FUNCTION "Gest Avvisi ed Allarmi" : VOID
TITLE =Gestione Avvisi ed Allarmi
AUTHOR : MassimoZ
FAMILY : NovaSrl
VERSION : 0.1

BEGIN
NETWORK
TITLE ======== Accatastatrice 1 =======

NETWORK
TITLE ======== Avvisi ======

NETWORK
TITLE =Avviso Manca Presenza Pallet al Carico Acc.1

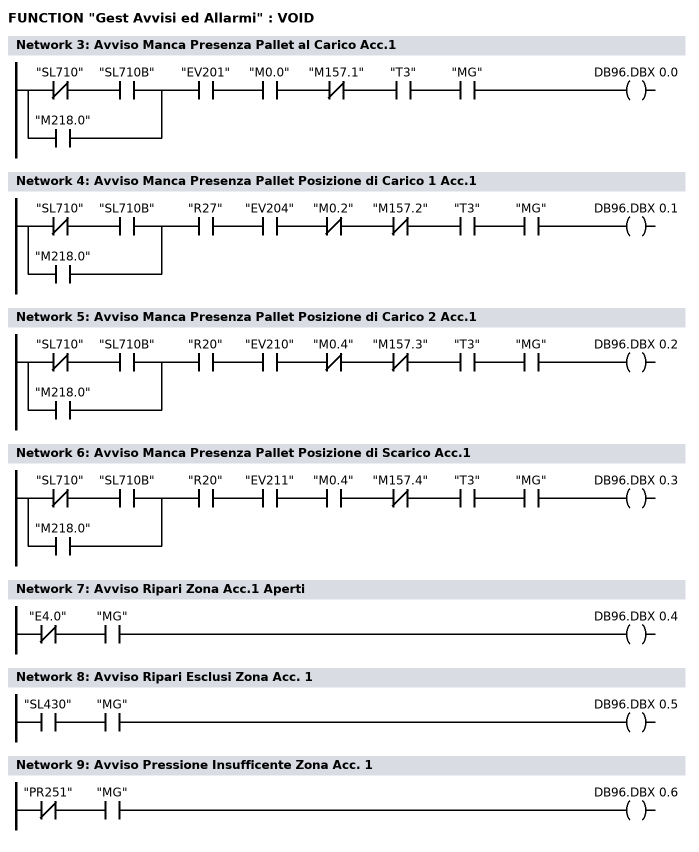
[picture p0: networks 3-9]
      U(    ;
      UN    "SL710";
      U     "SL710B";
      O     "M218.0";
      )     ;
      U     "EV201";
      U     "M0.0";
      UN    "M157.1";
      U     "T3";
      U     "MG";
      =     DB96.DBX    0.0;
NETWORK
TITLE =Avviso Manca Presenza Pallet Posizione di Carico 1 Acc.1

      U(    ;
      UN    "SL710";
      U     "SL710B";
      O     "M218.0";
      )     ;
      U     "R27";
      U     "EV204";
      UN    "M0.2";
      UN    "M157.2";
      U     "T3";
      U     "MG";
      =     DB96.DBX    0.1;
NETWORK
TITLE =Avviso Manca Presenza Pallet Posizione di Carico 2 Acc.1

      U(    ;
      UN    "SL710";
      U     "SL710B";
      O     "M218.0";
      )     ;
      U     "R20";
      U     "EV210";
      UN    "M0.4";
      UN    "M157.3";
      U     "T3";
      U     "MG";
      =     DB96.DBX    0.2;
NETWORK
TITLE =Avviso Manca Presenza Pallet Posizione di Scarico Acc.1

      U(    ;
      UN    "SL710";
      U     "SL710B";
      O     "M218.0";
      )     ;
      U     "R20";
      U     "EV211";
      U     "M0.4";
      UN    "M157.4";
      U     "T3";
      U     "MG";
      =     DB96.DBX    0.3;
NETWORK
TITLE =Avviso Ripari Zona Acc.1 Aperti

      UN    "E4.0";
      U     "MG";
      =     DB96.DBX    0.4;
NETWORK
TITLE =Avviso Ripari Esclusi Zona Acc. 1

      U     "SL430";
      U     "MG";
      =     DB96.DBX    0.5;
NETWORK
TITLE =Avviso Pressione Insufficente Zona Acc. 1

      UN    "PR251";
      U     "MG";
      =     DB96.DBX    0.6;
NETWORK
TITLE =Tempo di Verifica Avvisi Acc.1

      U     "ON";
      =     L      0.0;
      U     L      0.0;
      U(    ;
      UN    DB101.DBX    8.3;
      UN    DB101.DBX   28.3;
      O     ;
      UN    DB102.DBX    8.3;
      UN    DB102.DBX   28.3;
      O     ;
      UN    DB103.DBX    8.3;
      UN    DB103.DBX   28.3;
      O     ;
      UN    DB104.DBX    8.3;
      UN    DB104.DBX   28.3;
      O     M    242.7;
      )     ;
      =     DB96.DBX    0.7;
      U     L      0.0;
      U(    ;
      ON    DB130.DBX   18.1;
      ON    DB131.DBX   18.1;
      ON    DB132.DBX   18.1;
      ON    DB133.DBX   18.1;
      )     ;
      S     M    242.7;
      U(    ;
      U     L      0.0;
      U     DB102.DBX    8.3;
      FP    M    242.5;
      )     ;
      U     M    242.7;
      S     M    242.6;
      U     L      0.0;
      U     M    242.6;
      U     DB101.DBX   28.3;
      U     DB102.DBX   28.3;
      U     DB103.DBX   28.3;
      U     DB104.DBX   28.3;
      R     M    242.7;
      R     M    242.6;
NETWORK
TITLE ======== Allarmi ======

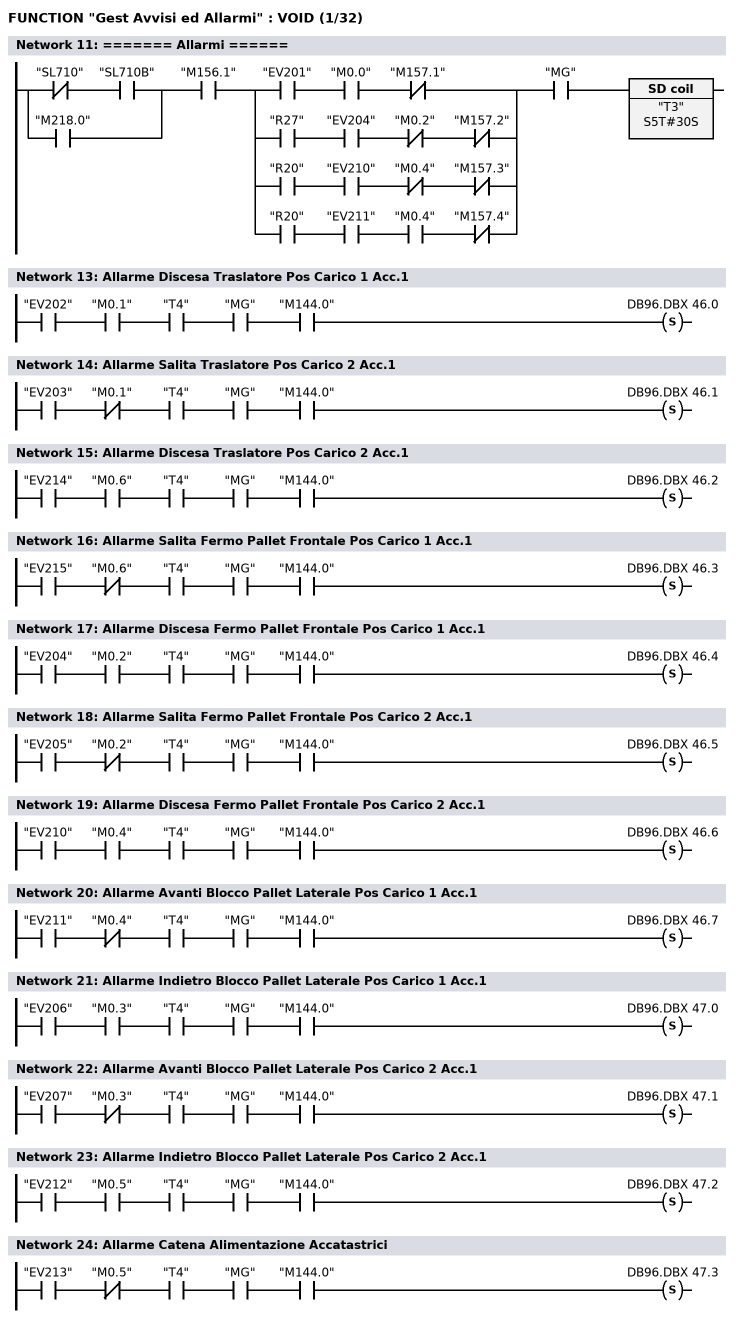
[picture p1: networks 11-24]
      U(    ;
      UN    "SL710";
      U     "SL710B";
      O     "M218.0";
      )     ;
      U     "M156.1";
      U(    ;
      U     "EV201";
      U     "M0.0";
      UN    "M157.1";
      O     ;
      U     "R27";
      U     "EV204";
      UN    "M0.2";
      UN    "M157.2";
      O     ;
      U     "R20";
      U     "EV210";
      UN    "M0.4";
      UN    "M157.3";
      O     ;
      U     "R20";
      U     "EV211";
      U     "M0.4";
      UN    "M157.4";
      )     ;
      U     "MG";
      L     S5T#30S;
      SE    "T3";
      NOP   0;
      NOP   0;
      NOP   0;
      NOP   0;
NETWORK
TITLE =Allarme Salita Traslatore Pos Carico 1 Acc.1

NETWORK
TITLE =Allarme Discesa Traslatore Pos Carico 1 Acc.1

      U     "EV202";
      U     "M0.1";
      U     "T4";
      U     "MG";
      U     "M144.0";
      S     DB96.DBX   46.0;
NETWORK
TITLE =Allarme Salita Traslatore Pos Carico 2 Acc.1

      U     "EV203";
      UN    "M0.1";
      U     "T4";
      U     "MG";
      U     "M144.0";
      S     DB96.DBX   46.1;
NETWORK
TITLE =Allarme Discesa Traslatore Pos Carico 2 Acc.1

      U     "EV214";
      U     "M0.6";
      U     "T4";
      U     "MG";
      U     "M144.0";
      S     DB96.DBX   46.2;
NETWORK
TITLE =Allarme Salita Fermo Pallet Frontale Pos Carico 1 Acc.1

      U     "EV215";
      UN    "M0.6";
      U     "T4";
      U     "MG";
      U     "M144.0";
      S     DB96.DBX   46.3;
NETWORK
TITLE =Allarme Discesa Fermo Pallet Frontale Pos Carico 1 Acc.1

      U     "EV204";
      U     "M0.2";
      U     "T4";
      U     "MG";
      U     "M144.0";
      S     DB96.DBX   46.4;
NETWORK
TITLE =Allarme Salita Fermo Pallet Frontale Pos Carico 2 Acc.1

      U     "EV205";
      UN    "M0.2";
      U     "T4";
      U     "MG";
      U     "M144.0";
      S     DB96.DBX   46.5;
NETWORK
TITLE =Allarme Discesa Fermo Pallet Frontale Pos Carico 2 Acc.1

      U     "EV210";
      U     "M0.4";
      U     "T4";
      U     "MG";
      U     "M144.0";
      S     DB96.DBX   46.6;
NETWORK
TITLE =Allarme Avanti Blocco Pallet Laterale Pos Carico 1 Acc.1

      U     "EV211";
      UN    "M0.4";
      U     "T4";
      U     "MG";
      U     "M144.0";
      S     DB96.DBX   46.7;
NETWORK
TITLE =Allarme Indietro Blocco Pallet Laterale Pos Carico 1 Acc.1

      U     "EV206";
      U     "M0.3";
      U     "T4";
      U     "MG";
      U     "M144.0";
      S     DB96.DBX   47.0;
NETWORK
TITLE =Allarme Avanti Blocco Pallet Laterale Pos Carico 2 Acc.1

      U     "EV207";
      UN    "M0.3";
      U     "T4";
      U     "MG";
      U     "M144.0";
      S     DB96.DBX   47.1;
NETWORK
TITLE =Allarme Indietro Blocco Pallet Laterale Pos Carico 2 Acc.1

      U     "EV212";
      U     "M0.5";
      U     "T4";
      U     "MG";
      U     "M144.0";
      S     DB96.DBX   47.2;
NETWORK
TITLE =Allarme Catena Alimentazione Accatastrici

      U     "EV213";
      UN    "M0.5";
      U     "T4";
      U     "MG";
      U     "M144.0";
      S     DB96.DBX   47.3;
NETWORK
TITLE =Allarme Catena Alimentazione Accatastrice 1

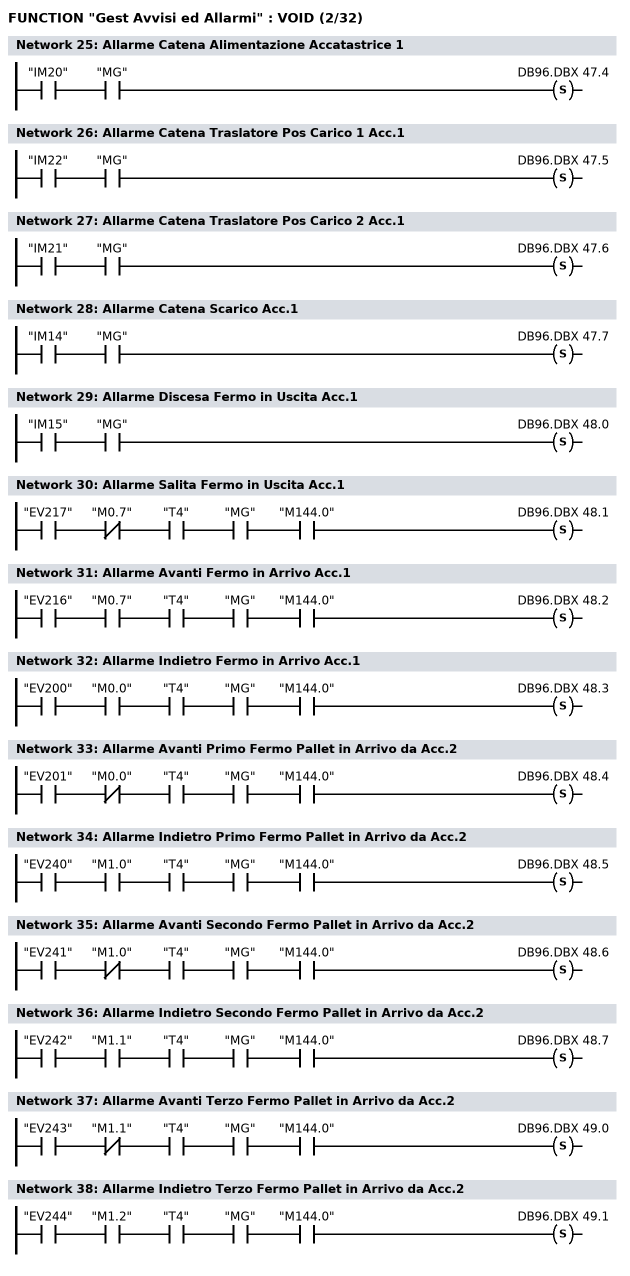
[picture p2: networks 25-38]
      U     "IM20";
      U     "MG";
      S     DB96.DBX   47.4;
NETWORK
TITLE =Allarme Catena Traslatore Pos Carico 1 Acc.1

      U     "IM22";
      U     "MG";
      S     DB96.DBX   47.5;
NETWORK
TITLE =Allarme Catena Traslatore Pos Carico 2 Acc.1

      U     "IM21";
      U     "MG";
      S     DB96.DBX   47.6;
NETWORK
TITLE =Allarme Catena Scarico Acc.1

      U     "IM14";
      U     "MG";
      S     DB96.DBX   47.7;
NETWORK
TITLE =Allarme Discesa Fermo in Uscita Acc.1

      U     "IM15";
      U     "MG";
      S     DB96.DBX   48.0;
NETWORK
TITLE =Allarme Salita Fermo in Uscita Acc.1

      U     "EV217";
      UN    "M0.7";
      U     "T4";
      U     "MG";
      U     "M144.0";
      S     DB96.DBX   48.1;
NETWORK
TITLE =Allarme Avanti Fermo in Arrivo Acc.1

      U     "EV216";
      U     "M0.7";
      U     "T4";
      U     "MG";
      U     "M144.0";
      S     DB96.DBX   48.2;
NETWORK
TITLE =Allarme Indietro Fermo in Arrivo Acc.1

      U     "EV200";
      U     "M0.0";
      U     "T4";
      U     "MG";
      U     "M144.0";
      S     DB96.DBX   48.3;
NETWORK
TITLE =Allarme Avanti Primo Fermo Pallet in Arrivo da Acc.2

      U     "EV201";
      UN    "M0.0";
      U     "T4";
      U     "MG";
      U     "M144.0";
      S     DB96.DBX   48.4;
NETWORK
TITLE =Allarme Indietro Primo Fermo Pallet in Arrivo da Acc.2

      U     "EV240";
      U     "M1.0";
      U     "T4";
      U     "MG";
      U     "M144.0";
      S     DB96.DBX   48.5;
NETWORK
TITLE =Allarme Avanti Secondo Fermo Pallet in Arrivo da Acc.2

      U     "EV241";
      UN    "M1.0";
      U     "T4";
      U     "MG";
      U     "M144.0";
      S     DB96.DBX   48.6;
NETWORK
TITLE =Allarme Indietro Secondo Fermo Pallet in Arrivo da Acc.2

      U     "EV242";
      U     "M1.1";
      U     "T4";
      U     "MG";
      U     "M144.0";
      S     DB96.DBX   48.7;
NETWORK
TITLE =Allarme Avanti Terzo Fermo Pallet in Arrivo da Acc.2

      U     "EV243";
      UN    "M1.1";
      U     "T4";
      U     "MG";
      U     "M144.0";
      S     DB96.DBX   49.0;
NETWORK
TITLE =Allarme Indietro Terzo Fermo Pallet in Arrivo da Acc.2

      U     "EV244";
      U     "M1.2";
      U     "T4";
      U     "MG";
      U     "M144.0";
      S     DB96.DBX   49.1;
NETWORK
TITLE =Tempo di Verifica Allarmi Acc.1

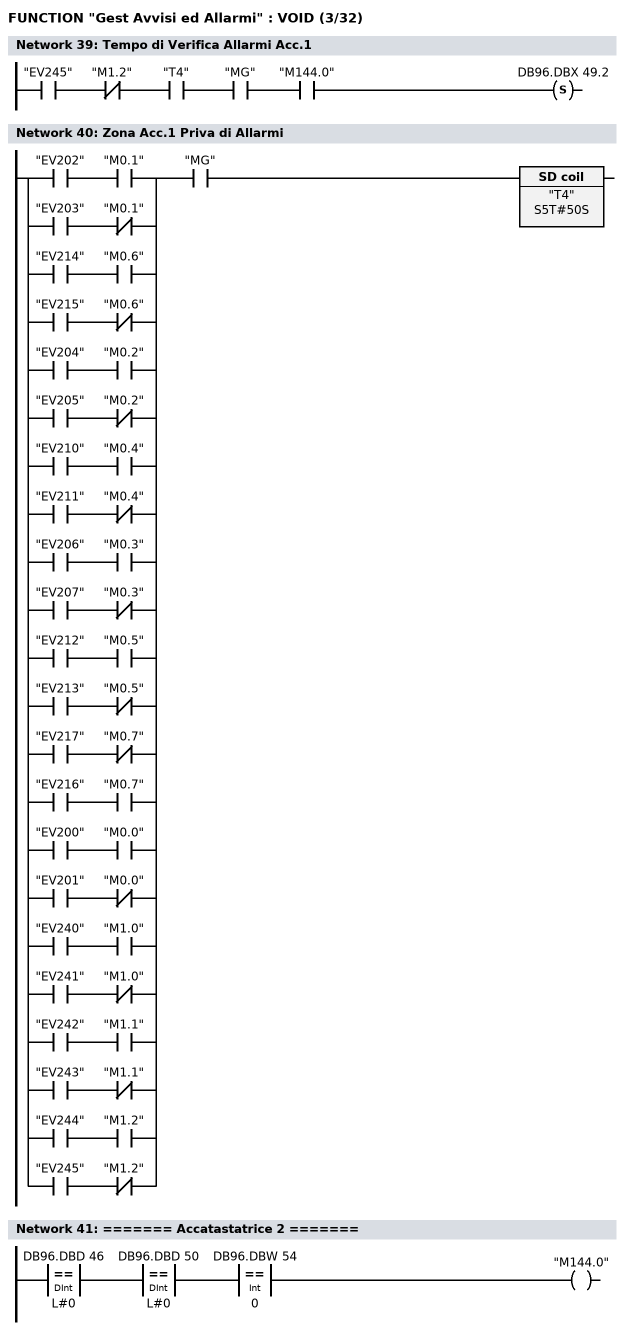
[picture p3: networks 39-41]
      U     "EV245";
      UN    "M1.2";
      U     "T4";
      U     "MG";
      U     "M144.0";
      S     DB96.DBX   49.2;
NETWORK
TITLE =Zona Acc.1 Priva di Allarmi

      U(    ;
      U     "EV202";
      U     "M0.1";
      O     ;
      U     "EV203";
      UN    "M0.1";
      O     ;
      U     "EV214";
      U     "M0.6";
      O     ;
      U     "EV215";
      UN    "M0.6";
      O     ;
      U     "EV204";
      U     "M0.2";
      O     ;
      U     "EV205";
      UN    "M0.2";
      O     ;
      U     "EV210";
      U     "M0.4";
      O     ;
      U     "EV211";
      UN    "M0.4";
      O     ;
      U     "EV206";
      U     "M0.3";
      O     ;
      U     "EV207";
      UN    "M0.3";
      O     ;
      U     "EV212";
      U     "M0.5";
      O     ;
      U     "EV213";
      UN    "M0.5";
      O     ;
      U     "EV217";
      UN    "M0.7";
      O     ;
      U     "EV216";
      U     "M0.7";
      O     ;
      U     "EV200";
      U     "M0.0";
      O     ;
      U     "EV201";
      UN    "M0.0";
      O     ;
      U     "EV240";
      U     "M1.0";
      O     ;
      U     "EV241";
      UN    "M1.0";
      O     ;
      U     "EV242";
      U     "M1.1";
      O     ;
      U     "EV243";
      UN    "M1.1";
      O     ;
      U     "EV244";
      U     "M1.2";
      O     ;
      U     "EV245";
      UN    "M1.2";
      )     ;
      U     "MG";
      L     S5T#50S;
      SE    "T4";
      NOP   0;
      NOP   0;
      NOP   0;
      NOP   0;
NETWORK
TITLE ======== Accatastatrice 2 =======

      U(    ;
      L     DB96.DBD   46;
      L     L#0;
      ==D   ;
      )     ;
      U(    ;
      L     DB96.DBD   50;
      L     L#0;
      ==D   ;
      )     ;
      U(    ;
      L     DB96.DBW   54;
      L     0;
      ==I   ;
      )     ;
      =     "M144.0";
NETWORK
TITLE ======== Avvisi ======

NETWORK
TITLE =Avviso Manca Presenza Pallet al Carico Acc.2

NETWORK
TITLE =Avviso Manca Presenza Pallet Posizione di Carico 1 Acc.2

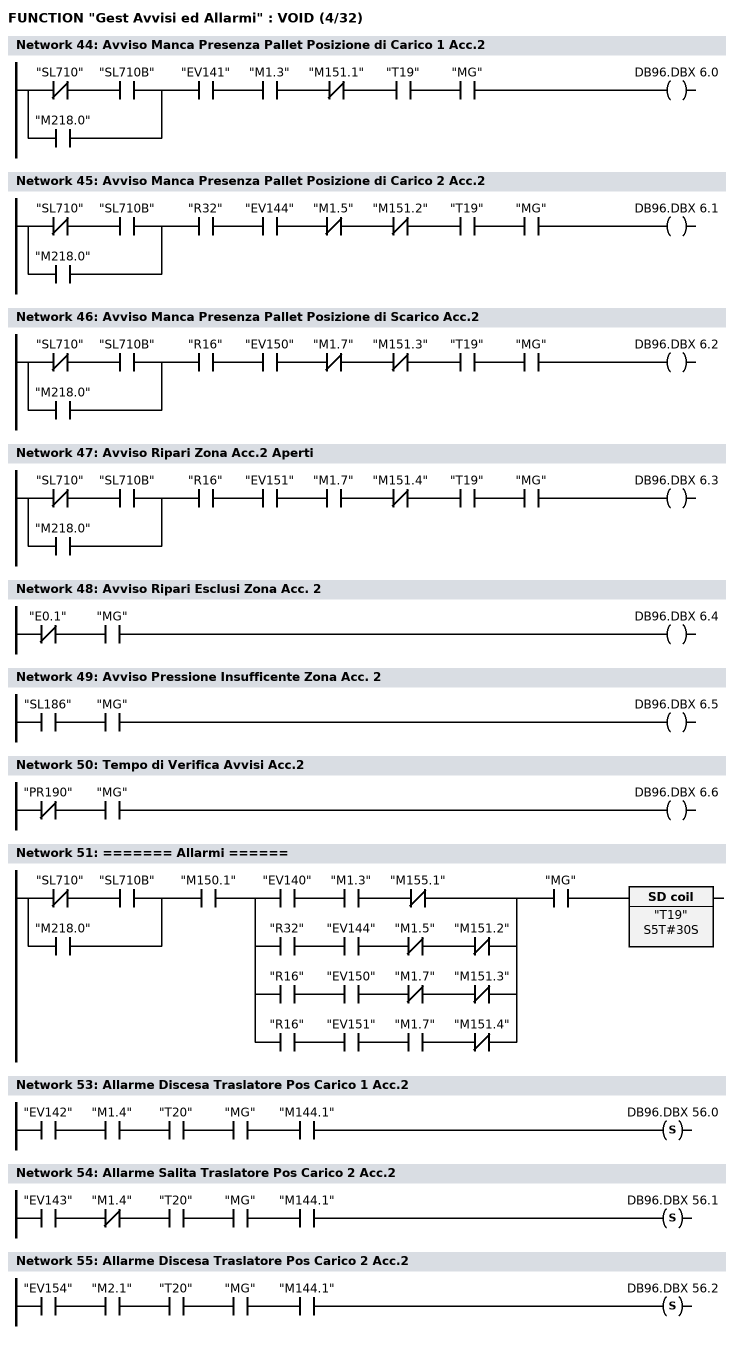
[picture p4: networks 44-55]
      U(    ;
      UN    "SL710";
      U     "SL710B";
      O     "M218.0";
      )     ;
      U     "EV141";
      U     "M1.3";
      UN    "M151.1";
      U     "T19";
      U     "MG";
      =     DB96.DBX    6.0;
NETWORK
TITLE =Avviso Manca Presenza Pallet Posizione di Carico 2 Acc.2

      U(    ;
      UN    "SL710";
      U     "SL710B";
      O     "M218.0";
      )     ;
      U     "R32";
      U     "EV144";
      UN    "M1.5";
      UN    "M151.2";
      U     "T19";
      U     "MG";
      =     DB96.DBX    6.1;
NETWORK
TITLE =Avviso Manca Presenza Pallet Posizione di Scarico Acc.2

      U(    ;
      UN    "SL710";
      U     "SL710B";
      O     "M218.0";
      )     ;
      U     "R16";
      U     "EV150";
      UN    "M1.7";
      UN    "M151.3";
      U     "T19";
      U     "MG";
      =     DB96.DBX    6.2;
NETWORK
TITLE =Avviso Ripari Zona Acc.2 Aperti

      U(    ;
      UN    "SL710";
      U     "SL710B";
      O     "M218.0";
      )     ;
      U     "R16";
      U     "EV151";
      U     "M1.7";
      UN    "M151.4";
      U     "T19";
      U     "MG";
      =     DB96.DBX    6.3;
NETWORK
TITLE =Avviso Ripari Esclusi Zona Acc. 2

      UN    "E0.1";
      U     "MG";
      =     DB96.DBX    6.4;
NETWORK
TITLE =Avviso Pressione Insufficente Zona Acc. 2

      U     "SL186";
      U     "MG";
      =     DB96.DBX    6.5;
NETWORK
TITLE =Tempo di Verifica Avvisi Acc.2

      UN    "PR190";
      U     "MG";
      =     DB96.DBX    6.6;
NETWORK
TITLE ======== Allarmi ======

      U(    ;
      UN    "SL710";
      U     "SL710B";
      O     "M218.0";
      )     ;
      U     "M150.1";
      U(    ;
      U     "EV140";
      U     "M1.3";
      UN    "M155.1";
      O     ;
      U     "R32";
      U     "EV144";
      UN    "M1.5";
      UN    "M151.2";
      O     ;
      U     "R16";
      U     "EV150";
      UN    "M1.7";
      UN    "M151.3";
      O     ;
      U     "R16";
      U     "EV151";
      U     "M1.7";
      UN    "M151.4";
      )     ;
      U     "MG";
      L     S5T#30S;
      SE    "T19";
      NOP   0;
      NOP   0;
      NOP   0;
      NOP   0;
NETWORK
TITLE =Allarme Salita Traslatore Pos Carico 1 Acc.2

NETWORK
TITLE =Allarme Discesa Traslatore Pos Carico 1 Acc.2

      U     "EV142";
      U     "M1.4";
      U     "T20";
      U     "MG";
      U     "M144.1";
      S     DB96.DBX   56.0;
NETWORK
TITLE =Allarme Salita Traslatore Pos Carico 2 Acc.2

      U     "EV143";
      UN    "M1.4";
      U     "T20";
      U     "MG";
      U     "M144.1";
      S     DB96.DBX   56.1;
NETWORK
TITLE =Allarme Discesa Traslatore Pos Carico 2 Acc.2

      U     "EV154";
      U     "M2.1";
      U     "T20";
      U     "MG";
      U     "M144.1";
      S     DB96.DBX   56.2;
NETWORK
TITLE =Allarme Salita Fermo Pallet Frontale Pos Carico 1 Acc.2

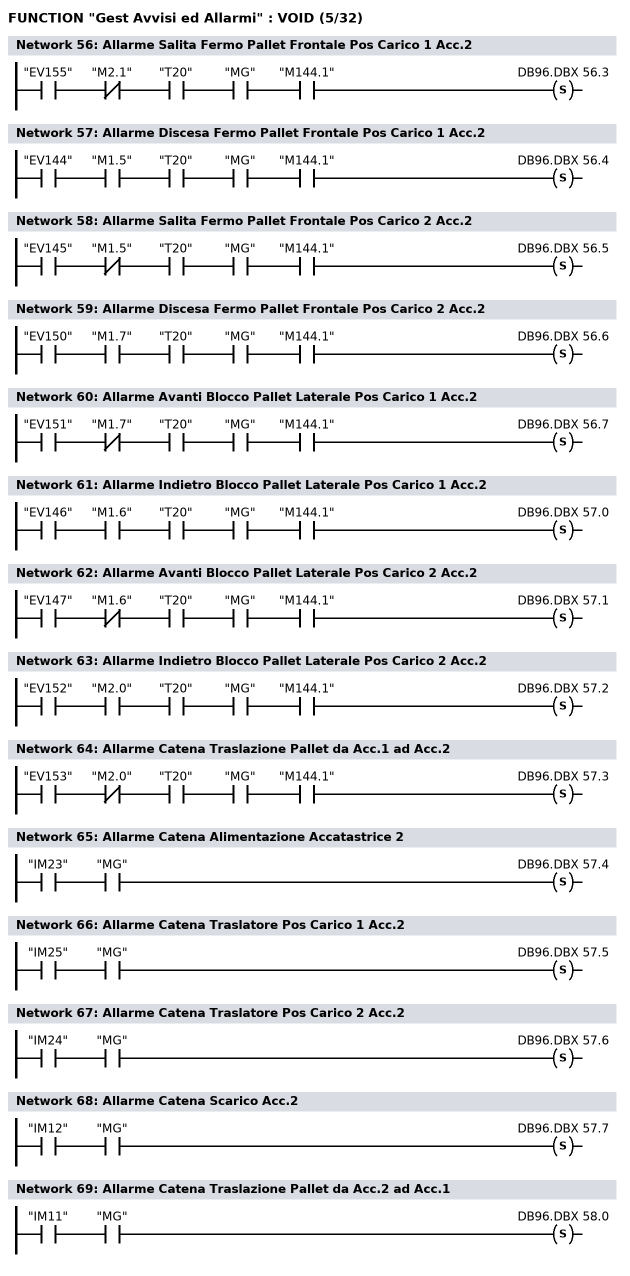
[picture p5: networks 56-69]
      U     "EV155";
      UN    "M2.1";
      U     "T20";
      U     "MG";
      U     "M144.1";
      S     DB96.DBX   56.3;
NETWORK
TITLE =Allarme Discesa Fermo Pallet Frontale Pos Carico 1 Acc.2

      U     "EV144";
      U     "M1.5";
      U     "T20";
      U     "MG";
      U     "M144.1";
      S     DB96.DBX   56.4;
NETWORK
TITLE =Allarme Salita Fermo Pallet Frontale Pos Carico 2 Acc.2

      U     "EV145";
      UN    "M1.5";
      U     "T20";
      U     "MG";
      U     "M144.1";
      S     DB96.DBX   56.5;
NETWORK
TITLE =Allarme Discesa Fermo Pallet Frontale Pos Carico 2 Acc.2

      U     "EV150";
      U     "M1.7";
      U     "T20";
      U     "MG";
      U     "M144.1";
      S     DB96.DBX   56.6;
NETWORK
TITLE =Allarme Avanti Blocco Pallet Laterale Pos Carico 1 Acc.2

      U     "EV151";
      UN    "M1.7";
      U     "T20";
      U     "MG";
      U     "M144.1";
      S     DB96.DBX   56.7;
NETWORK
TITLE =Allarme Indietro Blocco Pallet Laterale Pos Carico 1 Acc.2

      U     "EV146";
      U     "M1.6";
      U     "T20";
      U     "MG";
      U     "M144.1";
      S     DB96.DBX   57.0;
NETWORK
TITLE =Allarme Avanti Blocco Pallet Laterale Pos Carico 2 Acc.2

      U     "EV147";
      UN    "M1.6";
      U     "T20";
      U     "MG";
      U     "M144.1";
      S     DB96.DBX   57.1;
NETWORK
TITLE =Allarme Indietro Blocco Pallet Laterale Pos Carico 2 Acc.2

      U     "EV152";
      U     "M2.0";
      U     "T20";
      U     "MG";
      U     "M144.1";
      S     DB96.DBX   57.2;
NETWORK
TITLE =Allarme Catena Traslazione Pallet da Acc.1 ad Acc.2

      U     "EV153";
      UN    "M2.0";
      U     "T20";
      U     "MG";
      U     "M144.1";
      S     DB96.DBX   57.3;
NETWORK
TITLE =Allarme Catena Alimentazione Accatastrice 2

      U     "IM23";
      U     "MG";
      S     DB96.DBX   57.4;
NETWORK
TITLE =Allarme Catena Traslatore Pos Carico 1 Acc.2

      U     "IM25";
      U     "MG";
      S     DB96.DBX   57.5;
NETWORK
TITLE =Allarme Catena Traslatore Pos Carico 2 Acc.2

      U     "IM24";
      U     "MG";
      S     DB96.DBX   57.6;
NETWORK
TITLE =Allarme Catena Scarico Acc.2

      U     "IM12";
      U     "MG";
      S     DB96.DBX   57.7;
NETWORK
TITLE =Allarme Catena Traslazione Pallet da Acc.2 ad Acc.1

      U     "IM11";
      U     "MG";
      S     DB96.DBX   58.0;
NETWORK
TITLE =Allarme Avanti Fermo in Arrivo Acc.2

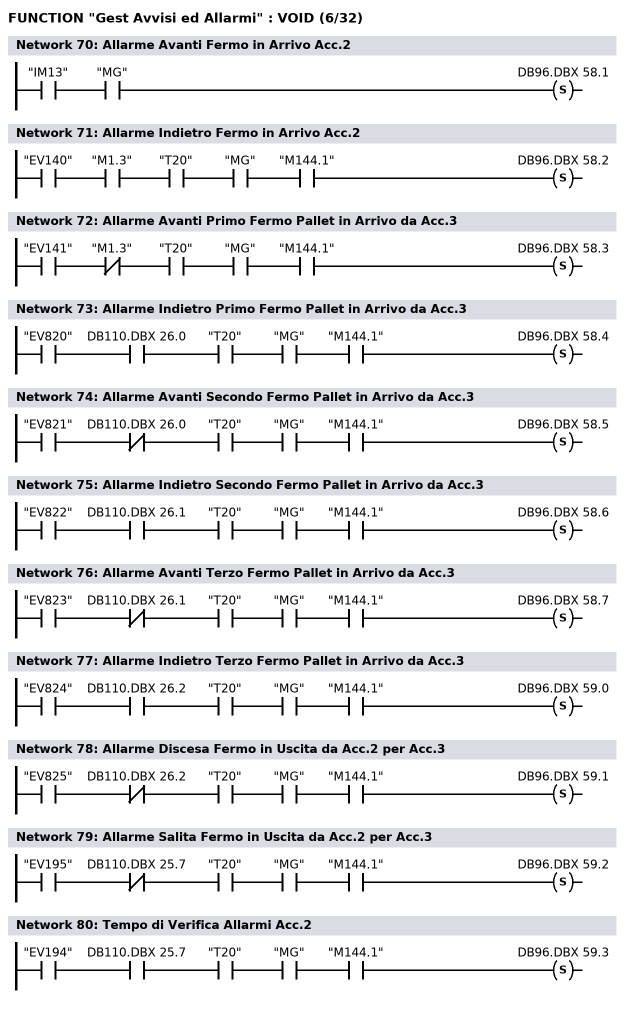
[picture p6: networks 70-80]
      U     "IM13";
      U     "MG";
      S     DB96.DBX   58.1;
NETWORK
TITLE =Allarme Indietro Fermo in Arrivo Acc.2

      U     "EV140";
      U     "M1.3";
      U     "T20";
      U     "MG";
      U     "M144.1";
      S     DB96.DBX   58.2;
NETWORK
TITLE =Allarme Avanti Primo Fermo Pallet in Arrivo da Acc.3

      U     "EV141";
      UN    "M1.3";
      U     "T20";
      U     "MG";
      U     "M144.1";
      S     DB96.DBX   58.3;
NETWORK
TITLE =Allarme Indietro Primo Fermo Pallet in Arrivo da Acc.3

      U     "EV820";
      U     DB110.DBX   26.0;
      U     "T20";
      U     "MG";
      U     "M144.1";
      S     DB96.DBX   58.4;
NETWORK
TITLE =Allarme Avanti Secondo Fermo Pallet in Arrivo da Acc.3

      U     "EV821";
      UN    DB110.DBX   26.0;
      U     "T20";
      U     "MG";
      U     "M144.1";
      S     DB96.DBX   58.5;
NETWORK
TITLE =Allarme Indietro Secondo Fermo Pallet in Arrivo da Acc.3

      U     "EV822";
      U     DB110.DBX   26.1;
      U     "T20";
      U     "MG";
      U     "M144.1";
      S     DB96.DBX   58.6;
NETWORK
TITLE =Allarme Avanti Terzo Fermo Pallet in Arrivo da Acc.3

      U     "EV823";
      UN    DB110.DBX   26.1;
      U     "T20";
      U     "MG";
      U     "M144.1";
      S     DB96.DBX   58.7;
NETWORK
TITLE =Allarme Indietro Terzo Fermo Pallet in Arrivo da Acc.3

      U     "EV824";
      U     DB110.DBX   26.2;
      U     "T20";
      U     "MG";
      U     "M144.1";
      S     DB96.DBX   59.0;
NETWORK
TITLE =Allarme Discesa Fermo in Uscita da Acc.2 per Acc.3

      U     "EV825";
      UN    DB110.DBX   26.2;
      U     "T20";
      U     "MG";
      U     "M144.1";
      S     DB96.DBX   59.1;
NETWORK
TITLE =Allarme Salita Fermo in Uscita da Acc.2 per Acc.3

      U     "EV195";
      UN    DB110.DBX   25.7;
      U     "T20";
      U     "MG";
      U     "M144.1";
      S     DB96.DBX   59.2;
NETWORK
TITLE =Tempo di Verifica Allarmi Acc.2

      U     "EV194";
      U     DB110.DBX   25.7;
      U     "T20";
      U     "MG";
      U     "M144.1";
      S     DB96.DBX   59.3;
NETWORK
TITLE =Zona Acc.2 Priva di Allarmi

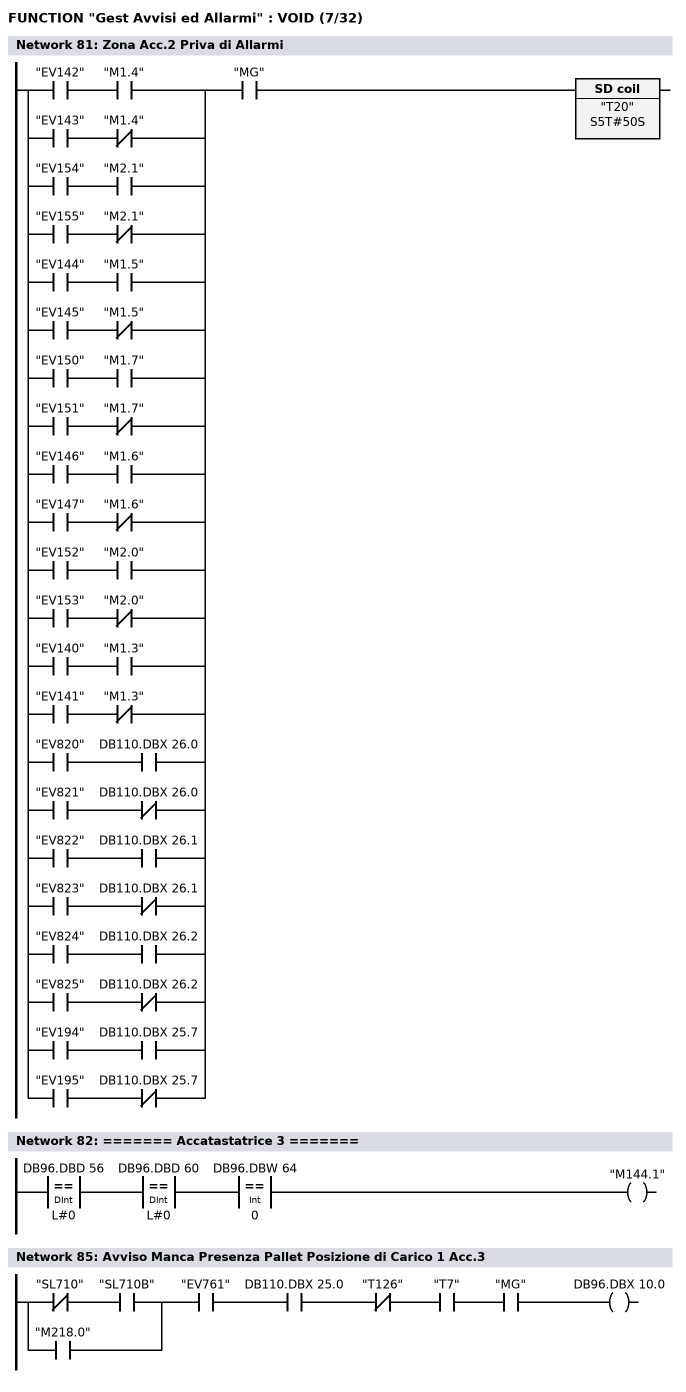
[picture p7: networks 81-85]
      U(    ;
      U     "EV142";
      U     "M1.4";
      O     ;
      U     "EV143";
      UN    "M1.4";
      O     ;
      U     "EV154";
      U     "M2.1";
      O     ;
      U     "EV155";
      UN    "M2.1";
      O     ;
      U     "EV144";
      U     "M1.5";
      O     ;
      U     "EV145";
      UN    "M1.5";
      O     ;
      U     "EV150";
      U     "M1.7";
      O     ;
      U     "EV151";
      UN    "M1.7";
      O     ;
      U     "EV146";
      U     "M1.6";
      O     ;
      U     "EV147";
      UN    "M1.6";
      O     ;
      U     "EV152";
      U     "M2.0";
      O     ;
      U     "EV153";
      UN    "M2.0";
      O     ;
      U     "EV140";
      U     "M1.3";
      O     ;
      U     "EV141";
      UN    "M1.3";
      O     ;
      U     "EV820";
      U     DB110.DBX   26.0;
      O     ;
      U     "EV821";
      UN    DB110.DBX   26.0;
      O     ;
      U     "EV822";
      U     DB110.DBX   26.1;
      O     ;
      U     "EV823";
      UN    DB110.DBX   26.1;
      O     ;
      U     "EV824";
      U     DB110.DBX   26.2;
      O     ;
      U     "EV825";
      UN    DB110.DBX   26.2;
      O     ;
      U     "EV194";
      U     DB110.DBX   25.7;
      O     ;
      U     "EV195";
      UN    DB110.DBX   25.7;
      )     ;
      U     "MG";
      L     S5T#50S;
      SE    "T20";
      NOP   0;
      NOP   0;
      NOP   0;
      NOP   0;
NETWORK
TITLE ======== Accatastatrice 3 =======

      U(    ;
      L     DB96.DBD   56;
      L     L#0;
      ==D   ;
      )     ;
      U(    ;
      L     DB96.DBD   60;
      L     L#0;
      ==D   ;
      )     ;
      U(    ;
      L     DB96.DBW   64;
      L     0;
      ==I   ;
      )     ;
      =     "M144.1";
NETWORK
TITLE ======== Avvisi ======

NETWORK
TITLE =Avviso Manca Presenza Pallet al Carico Acc.3

NETWORK
TITLE =Avviso Manca Presenza Pallet Posizione di Carico 1 Acc.3

      U(    ;
      UN    "SL710";
      U     "SL710B";
      O     "M218.0";
      )     ;
      U     "EV761";
      U     DB110.DBX   25.0;
      UN    "T126";
      U     "T7";
      U     "MG";
      =     DB96.DBX   10.0;
NETWORK
TITLE =Avviso Manca Presenza Pallet Posizione di Carico 2 Acc.3

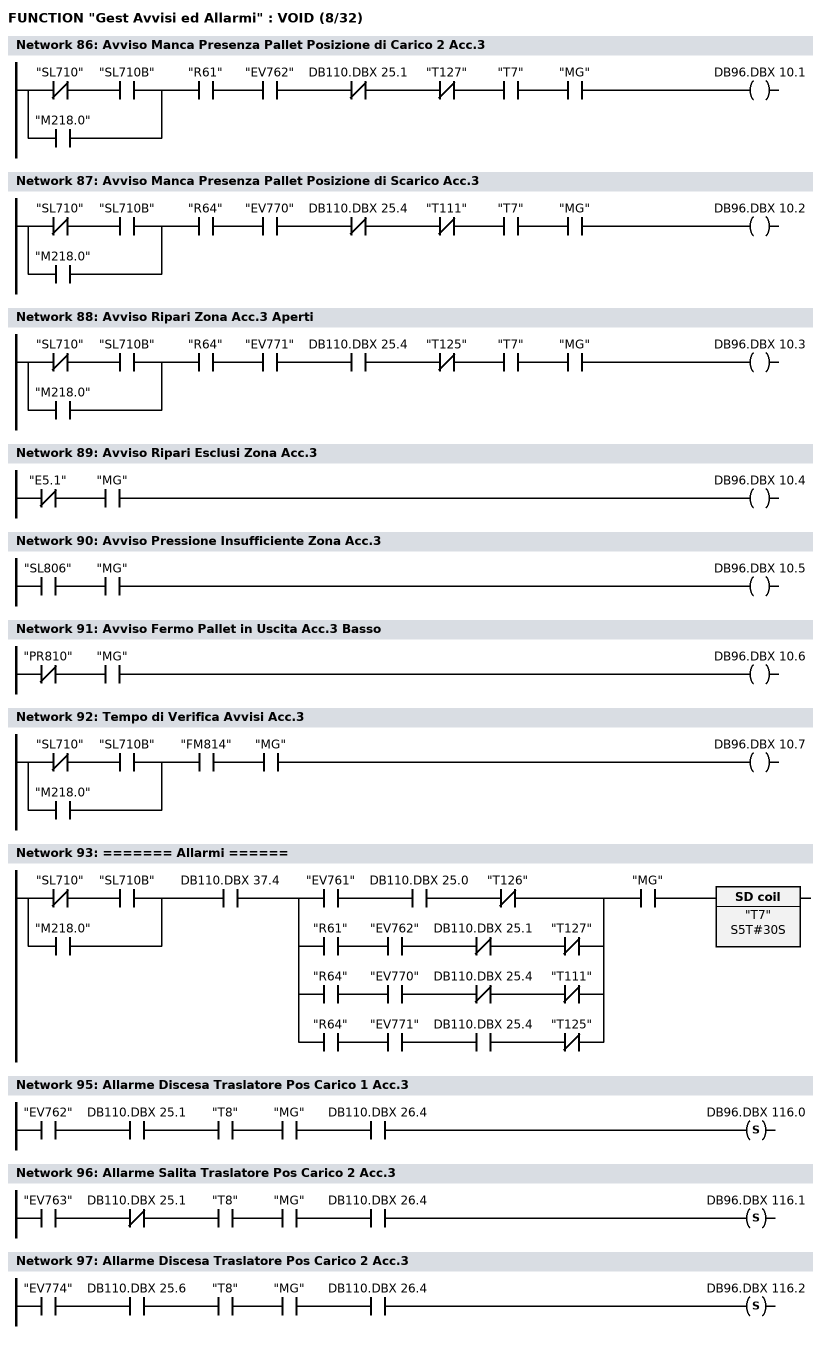
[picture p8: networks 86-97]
      U(    ;
      UN    "SL710";
      U     "SL710B";
      O     "M218.0";
      )     ;
      U     "R61";
      U     "EV762";
      UN    DB110.DBX   25.1;
      UN    "T127";
      U     "T7";
      U     "MG";
      =     DB96.DBX   10.1;
NETWORK
TITLE =Avviso Manca Presenza Pallet Posizione di Scarico Acc.3

      U(    ;
      UN    "SL710";
      U     "SL710B";
      O     "M218.0";
      )     ;
      U     "R64";
      U     "EV770";
      UN    DB110.DBX   25.4;
      UN    "T111";
      U     "T7";
      U     "MG";
      =     DB96.DBX   10.2;
NETWORK
TITLE =Avviso Ripari Zona Acc.3 Aperti

      U(    ;
      UN    "SL710";
      U     "SL710B";
      O     "M218.0";
      )     ;
      U     "R64";
      U     "EV771";
      U     DB110.DBX   25.4;
      UN    "T125";
      U     "T7";
      U     "MG";
      =     DB96.DBX   10.3;
NETWORK
TITLE =Avviso Ripari Esclusi Zona Acc.3

      UN    "E5.1";
      U     "MG";
      =     DB96.DBX   10.4;
NETWORK
TITLE =Avviso Pressione Insufficiente Zona Acc.3

      U     "SL806";
      U     "MG";
      =     DB96.DBX   10.5;
NETWORK
TITLE =Avviso Fermo Pallet in Uscita Acc.3 Basso

      UN    "PR810";
      U     "MG";
      =     DB96.DBX   10.6;
NETWORK
TITLE =Tempo di Verifica Avvisi Acc.3

      U(    ;
      UN    "SL710";
      U     "SL710B";
      O     "M218.0";
      )     ;
      U     "FM814";
      U     "MG";
      =     DB96.DBX   10.7;
NETWORK
TITLE ======== Allarmi ======

      U(    ;
      UN    "SL710";
      U     "SL710B";
      O     "M218.0";
      )     ;
      U     DB110.DBX   37.4;
      U(    ;
      U     "EV761";
      U     DB110.DBX   25.0;
      UN    "T126";
      O     ;
      U     "R61";
      U     "EV762";
      UN    DB110.DBX   25.1;
      UN    "T127";
      O     ;
      U     "R64";
      U     "EV770";
      UN    DB110.DBX   25.4;
      UN    "T111";
      O     ;
      U     "R64";
      U     "EV771";
      U     DB110.DBX   25.4;
      UN    "T125";
      )     ;
      U     "MG";
      L     S5T#30S;
      SE    "T7";
      NOP   0;
      NOP   0;
      NOP   0;
      NOP   0;
NETWORK
TITLE =Allarme Salita Traslatore Pos Carico 1 Acc.3

NETWORK
TITLE =Allarme Discesa Traslatore Pos Carico 1 Acc.3

      U     "EV762";
      U     DB110.DBX   25.1;
      U     "T8";
      U     "MG";
      U     DB110.DBX   26.4;
      S     DB96.DBX  116.0;
NETWORK
TITLE =Allarme Salita Traslatore Pos Carico 2 Acc.3

      U     "EV763";
      UN    DB110.DBX   25.1;
      U     "T8";
      U     "MG";
      U     DB110.DBX   26.4;
      S     DB96.DBX  116.1;
NETWORK
TITLE =Allarme Discesa Traslatore Pos Carico 2 Acc.3

      U     "EV774";
      U     DB110.DBX   25.6;
      U     "T8";
      U     "MG";
      U     DB110.DBX   26.4;
      S     DB96.DBX  116.2;
NETWORK
TITLE =Allarme Salita Fermo Pallet Frontale Pos Carico 1 Acc.3

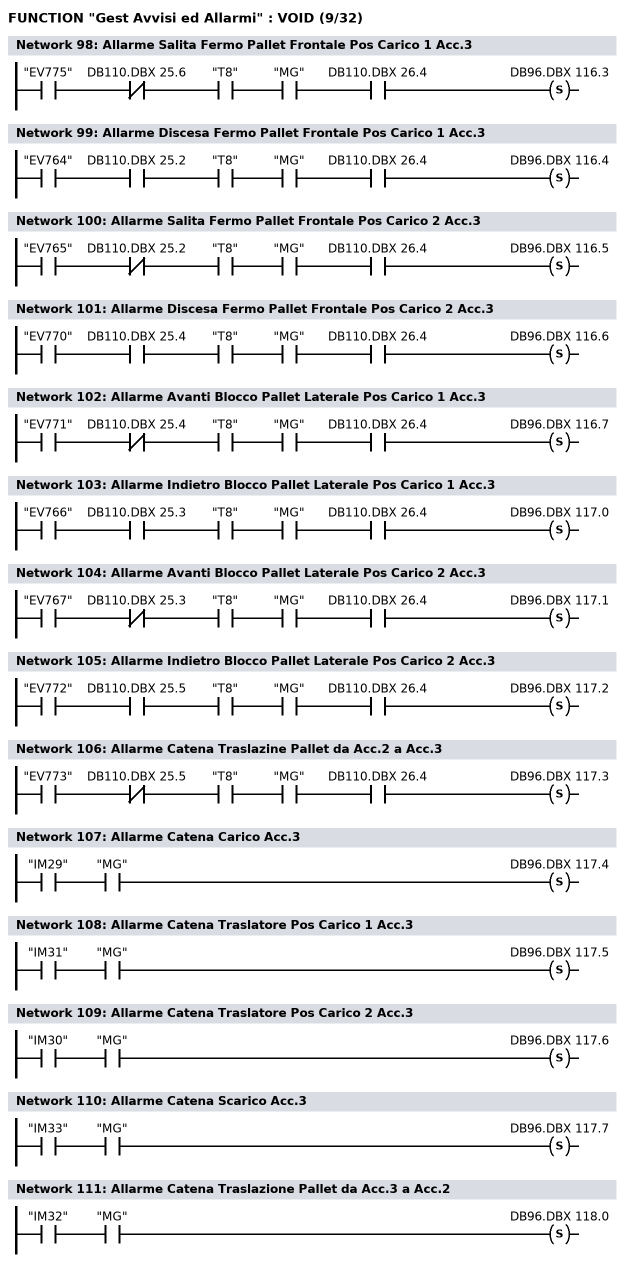
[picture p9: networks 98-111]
      U     "EV775";
      UN    DB110.DBX   25.6;
      U     "T8";
      U     "MG";
      U     DB110.DBX   26.4;
      S     DB96.DBX  116.3;
NETWORK
TITLE =Allarme Discesa Fermo Pallet Frontale Pos Carico 1 Acc.3

      U     "EV764";
      U     DB110.DBX   25.2;
      U     "T8";
      U     "MG";
      U     DB110.DBX   26.4;
      S     DB96.DBX  116.4;
NETWORK
TITLE =Allarme Salita Fermo Pallet Frontale Pos Carico 2 Acc.3

      U     "EV765";
      UN    DB110.DBX   25.2;
      U     "T8";
      U     "MG";
      U     DB110.DBX   26.4;
      S     DB96.DBX  116.5;
NETWORK
TITLE =Allarme Discesa Fermo Pallet Frontale Pos Carico 2 Acc.3

      U     "EV770";
      U     DB110.DBX   25.4;
      U     "T8";
      U     "MG";
      U     DB110.DBX   26.4;
      S     DB96.DBX  116.6;
NETWORK
TITLE =Allarme Avanti Blocco Pallet Laterale Pos Carico 1 Acc.3

      U     "EV771";
      UN    DB110.DBX   25.4;
      U     "T8";
      U     "MG";
      U     DB110.DBX   26.4;
      S     DB96.DBX  116.7;
NETWORK
TITLE =Allarme Indietro Blocco Pallet Laterale Pos Carico 1 Acc.3

      U     "EV766";
      U     DB110.DBX   25.3;
      U     "T8";
      U     "MG";
      U     DB110.DBX   26.4;
      S     DB96.DBX  117.0;
NETWORK
TITLE =Allarme Avanti Blocco Pallet Laterale Pos Carico 2 Acc.3

      U     "EV767";
      UN    DB110.DBX   25.3;
      U     "T8";
      U     "MG";
      U     DB110.DBX   26.4;
      S     DB96.DBX  117.1;
NETWORK
TITLE =Allarme Indietro Blocco Pallet Laterale Pos Carico 2 Acc.3

      U     "EV772";
      U     DB110.DBX   25.5;
      U     "T8";
      U     "MG";
      U     DB110.DBX   26.4;
      S     DB96.DBX  117.2;
NETWORK
TITLE =Allarme Catena Traslazine Pallet da Acc.2 a Acc.3

      U     "EV773";
      UN    DB110.DBX   25.5;
      U     "T8";
      U     "MG";
      U     DB110.DBX   26.4;
      S     DB96.DBX  117.3;
NETWORK
TITLE =Allarme Catena Carico Acc.3

      U     "IM29";
      U     "MG";
      S     DB96.DBX  117.4;
NETWORK
TITLE =Allarme Catena Traslatore Pos Carico 1 Acc.3

      U     "IM31";
      U     "MG";
      S     DB96.DBX  117.5;
NETWORK
TITLE =Allarme Catena Traslatore Pos Carico 2 Acc.3

      U     "IM30";
      U     "MG";
      S     DB96.DBX  117.6;
NETWORK
TITLE =Allarme Catena Scarico Acc.3

      U     "IM33";
      U     "MG";
      S     DB96.DBX  117.7;
NETWORK
TITLE =Allarme Catena Traslazione Pallet da Acc.3 a Acc.2

      U     "IM32";
      U     "MG";
      S     DB96.DBX  118.0;
NETWORK
TITLE =Allarme Avanti Fermo in Arrivo Acc.3

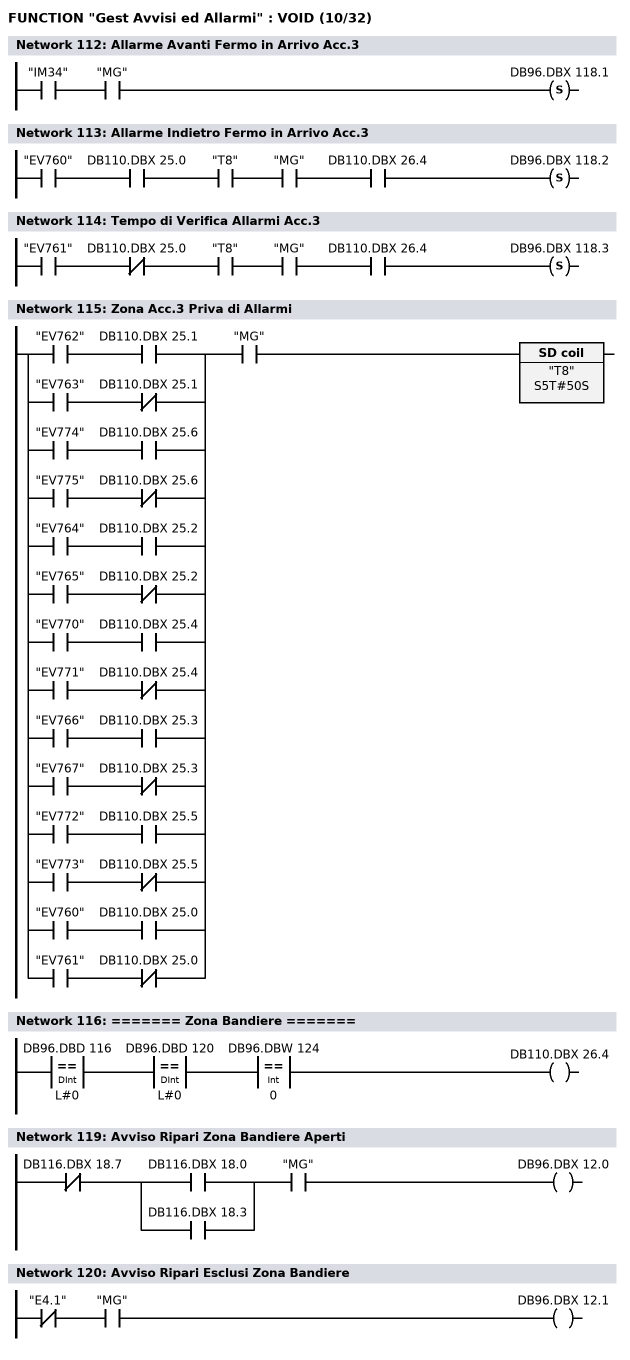
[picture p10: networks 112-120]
      U     "IM34";
      U     "MG";
      S     DB96.DBX  118.1;
NETWORK
TITLE =Allarme Indietro Fermo in Arrivo Acc.3

      U     "EV760";
      U     DB110.DBX   25.0;
      U     "T8";
      U     "MG";
      U     DB110.DBX   26.4;
      S     DB96.DBX  118.2;
NETWORK
TITLE =Tempo di Verifica Allarmi Acc.3

      U     "EV761";
      UN    DB110.DBX   25.0;
      U     "T8";
      U     "MG";
      U     DB110.DBX   26.4;
      S     DB96.DBX  118.3;
NETWORK
TITLE =Zona Acc.3 Priva di Allarmi

      U(    ;
      U     "EV762";
      U     DB110.DBX   25.1;
      O     ;
      U     "EV763";
      UN    DB110.DBX   25.1;
      O     ;
      U     "EV774";
      U     DB110.DBX   25.6;
      O     ;
      U     "EV775";
      UN    DB110.DBX   25.6;
      O     ;
      U     "EV764";
      U     DB110.DBX   25.2;
      O     ;
      U     "EV765";
      UN    DB110.DBX   25.2;
      O     ;
      U     "EV770";
      U     DB110.DBX   25.4;
      O     ;
      U     "EV771";
      UN    DB110.DBX   25.4;
      O     ;
      U     "EV766";
      U     DB110.DBX   25.3;
      O     ;
      U     "EV767";
      UN    DB110.DBX   25.3;
      O     ;
      U     "EV772";
      U     DB110.DBX   25.5;
      O     ;
      U     "EV773";
      UN    DB110.DBX   25.5;
      O     ;
      U     "EV760";
      U     DB110.DBX   25.0;
      O     ;
      U     "EV761";
      UN    DB110.DBX   25.0;
      )     ;
      U     "MG";
      L     S5T#50S;
      SE    "T8";
      NOP   0;
      NOP   0;
      NOP   0;
      NOP   0;
NETWORK
TITLE ======== Zona Bandiere =======

      U(    ;
      L     DB96.DBD  116;
      L     L#0;
      ==D   ;
      )     ;
      U(    ;
      L     DB96.DBD  120;
      L     L#0;
      ==D   ;
      )     ;
      U(    ;
      L     DB96.DBW  124;
      L     0;
      ==I   ;
      )     ;
      =     DB110.DBX   26.4;
NETWORK
TITLE ======== Avvisi ======

NETWORK
TITLE =Avviso Ascensore C.O.S. non in posizione bassa

NETWORK
TITLE =Avviso Ripari Zona Bandiere Aperti

      UN    DB116.DBX   18.7;
      U(    ;
      O     DB116.DBX   18.0;
      O     DB116.DBX   18.3;
      )     ;
      U     "MG";
      =     DB96.DBX   12.0;
NETWORK
TITLE =Avviso Ripari Esclusi Zona Bandiere

      UN    "E4.1";
      U     "MG";
      =     DB96.DBX   12.1;
NETWORK
TITLE =Avviso Pressione Insufficente Zona Bandiere

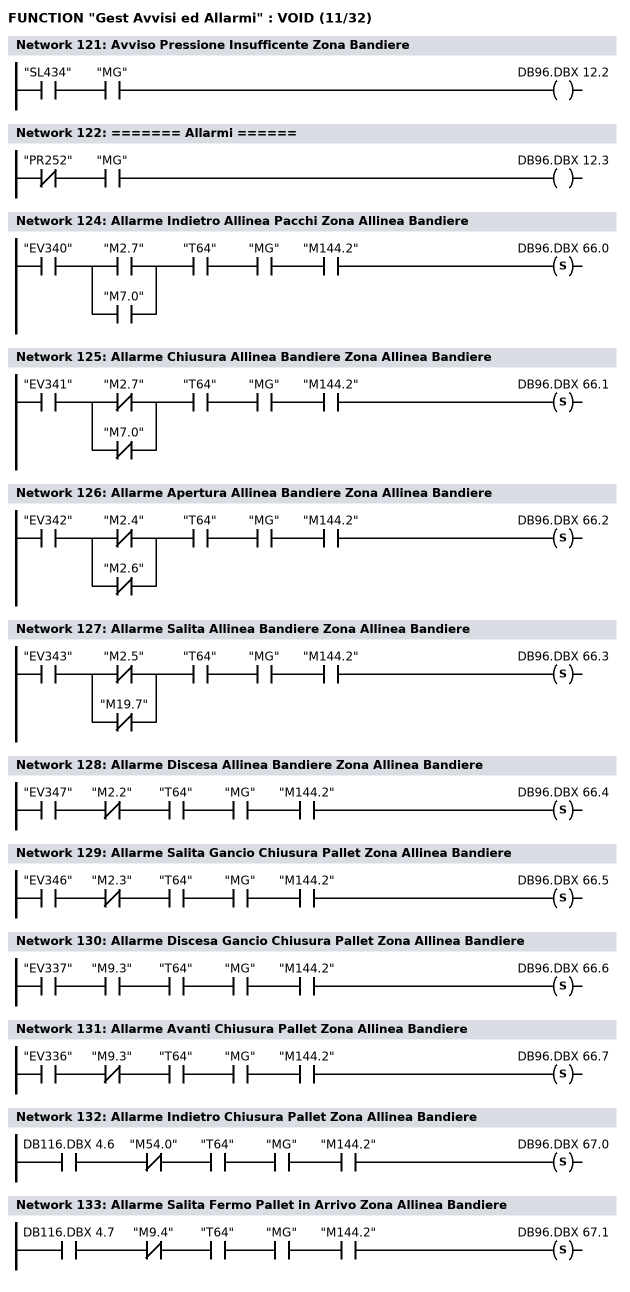
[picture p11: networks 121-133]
      U     "SL434";
      U     "MG";
      =     DB96.DBX   12.2;
NETWORK
TITLE ======== Allarmi ======

      UN    "PR252";
      U     "MG";
      =     DB96.DBX   12.3;
NETWORK
TITLE =Allarme Avanti Allinea Pacchi Zona Allinea Bandiere

NETWORK
TITLE =Allarme Indietro Allinea Pacchi Zona Allinea Bandiere

      U     "EV340";
      U(    ;
      O     "M2.7";
      O     "M7.0";
      )     ;
      U     "T64";
      U     "MG";
      U     "M144.2";
      S     DB96.DBX   66.0;
NETWORK
TITLE =Allarme Chiusura Allinea Bandiere Zona Allinea Bandiere

      U     "EV341";
      U(    ;
      ON    "M2.7";
      ON    "M7.0";
      )     ;
      U     "T64";
      U     "MG";
      U     "M144.2";
      S     DB96.DBX   66.1;
NETWORK
TITLE =Allarme Apertura Allinea Bandiere Zona Allinea Bandiere

      U     "EV342";
      U(    ;
      ON    "M2.4";
      ON    "M2.6";
      )     ;
      U     "T64";
      U     "MG";
      U     "M144.2";
      S     DB96.DBX   66.2;
NETWORK
TITLE =Allarme Salita Allinea Bandiere Zona Allinea Bandiere

      U     "EV343";
      U(    ;
      ON    "M2.5";
      ON    "M19.7";
      )     ;
      U     "T64";
      U     "MG";
      U     "M144.2";
      S     DB96.DBX   66.3;
NETWORK
TITLE =Allarme Discesa Allinea Bandiere Zona Allinea Bandiere

      U     "EV347";
      UN    "M2.2";
      U     "T64";
      U     "MG";
      U     "M144.2";
      S     DB96.DBX   66.4;
NETWORK
TITLE =Allarme Salita Gancio Chiusura Pallet Zona Allinea Bandiere

      U     "EV346";
      UN    "M2.3";
      U     "T64";
      U     "MG";
      U     "M144.2";
      S     DB96.DBX   66.5;
NETWORK
TITLE =Allarme Discesa Gancio Chiusura Pallet Zona Allinea Bandiere

      U     "EV337";
      U     "M9.3";
      U     "T64";
      U     "MG";
      U     "M144.2";
      S     DB96.DBX   66.6;
NETWORK
TITLE =Allarme Avanti Chiusura Pallet Zona Allinea Bandiere

      U     "EV336";
      UN    "M9.3";
      U     "T64";
      U     "MG";
      U     "M144.2";
      S     DB96.DBX   66.7;
NETWORK
TITLE =Allarme Indietro Chiusura Pallet Zona Allinea Bandiere

      U     DB116.DBX    4.6;
      UN    "M54.0";
      U     "T64";
      U     "MG";
      U     "M144.2";
      S     DB96.DBX   67.0;
NETWORK
TITLE =Allarme Salita Fermo Pallet in Arrivo Zona Allinea Bandiere

      U     DB116.DBX    4.7;
      UN    "M9.4";
      U     "T64";
      U     "MG";
      U     "M144.2";
      S     DB96.DBX   67.1;
NETWORK
TITLE =Allarme Discesa Fermo Pallet in Arrivo Zona Allinea Bandiere

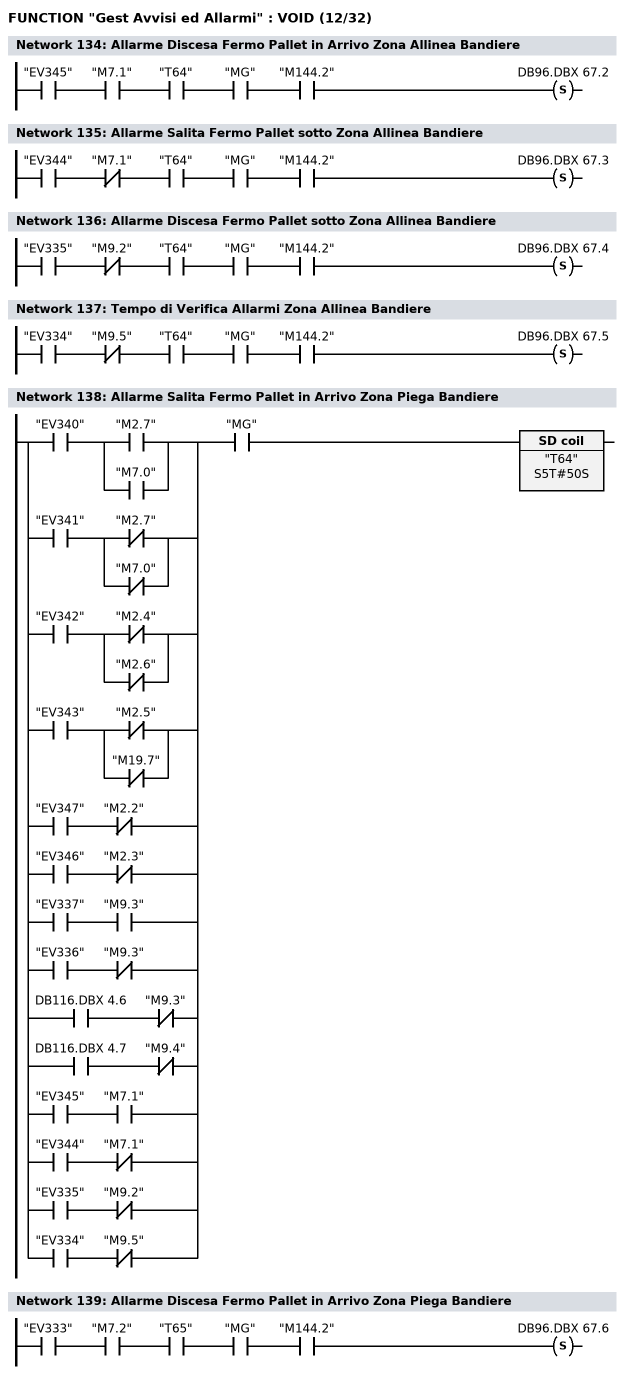
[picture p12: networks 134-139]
      U     "EV345";
      U     "M7.1";
      U     "T64";
      U     "MG";
      U     "M144.2";
      S     DB96.DBX   67.2;
NETWORK
TITLE =Allarme Salita Fermo Pallet sotto Zona Allinea Bandiere

      U     "EV344";
      UN    "M7.1";
      U     "T64";
      U     "MG";
      U     "M144.2";
      S     DB96.DBX   67.3;
NETWORK
TITLE =Allarme Discesa Fermo Pallet sotto Zona Allinea Bandiere

      U     "EV335";
      UN    "M9.2";
      U     "T64";
      U     "MG";
      U     "M144.2";
      S     DB96.DBX   67.4;
NETWORK
TITLE =Tempo di Verifica Allarmi Zona Allinea Bandiere

      U     "EV334";
      UN    "M9.5";
      U     "T64";
      U     "MG";
      U     "M144.2";
      S     DB96.DBX   67.5;
NETWORK
TITLE =Allarme Salita Fermo Pallet in Arrivo Zona Piega Bandiere

      U(    ;
      U     "EV340";
      U(    ;
      O     "M2.7";
      O     "M7.0";
      )     ;
      O     ;
      U     "EV341";
      U(    ;
      ON    "M2.7";
      ON    "M7.0";
      )     ;
      O     ;
      U     "EV342";
      U(    ;
      ON    "M2.4";
      ON    "M2.6";
      )     ;
      O     ;
      U     "EV343";
      U(    ;
      ON    "M2.5";
      ON    "M19.7";
      )     ;
      O     ;
      U     "EV347";
      UN    "M2.2";
      O     ;
      U     "EV346";
      UN    "M2.3";
      O     ;
      U     "EV337";
      U     "M9.3";
      O     ;
      U     "EV336";
      UN    "M9.3";
      O     ;
      U     DB116.DBX    4.6;
      UN    "M9.3";
      O     ;
      U     DB116.DBX    4.7;
      UN    "M9.4";
      O     ;
      U     "EV345";
      U     "M7.1";
      O     ;
      U     "EV344";
      UN    "M7.1";
      O     ;
      U     "EV335";
      UN    "M9.2";
      O     ;
      U     "EV334";
      UN    "M9.5";
      )     ;
      U     "MG";
      L     S5T#50S;
      SE    "T64";
      NOP   0;
      NOP   0;
      NOP   0;
      NOP   0;
NETWORK
TITLE =Allarme Discesa Fermo Pallet in Arrivo Zona Piega Bandiere

      U     "EV333";
      U     "M7.2";
      U     "T65";
      U     "MG";
      U     "M144.2";
      S     DB96.DBX   67.6;
NETWORK
TITLE =Allarme Salita Fermo Pallet sotto Zona Piega Bandiere

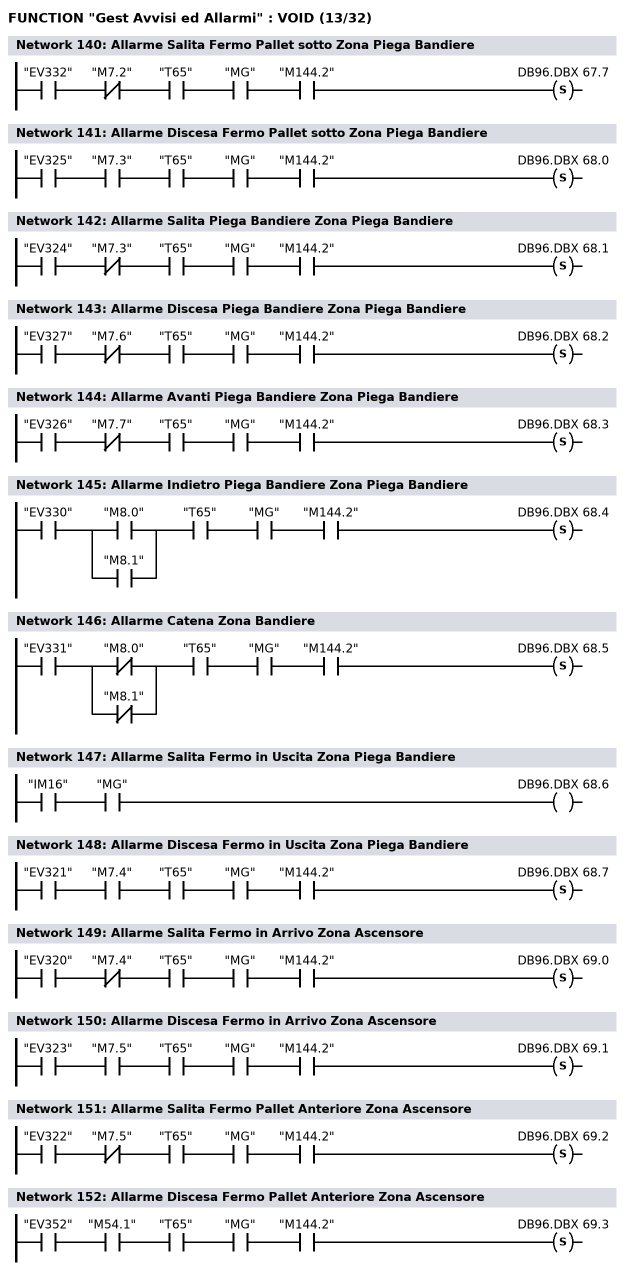
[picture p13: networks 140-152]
      U     "EV332";
      UN    "M7.2";
      U     "T65";
      U     "MG";
      U     "M144.2";
      S     DB96.DBX   67.7;
NETWORK
TITLE =Allarme Discesa Fermo Pallet sotto Zona Piega Bandiere

      U     "EV325";
      U     "M7.3";
      U     "T65";
      U     "MG";
      U     "M144.2";
      S     DB96.DBX   68.0;
NETWORK
TITLE =Allarme Salita Piega Bandiere Zona Piega Bandiere

      U     "EV324";
      UN    "M7.3";
      U     "T65";
      U     "MG";
      U     "M144.2";
      S     DB96.DBX   68.1;
NETWORK
TITLE =Allarme Discesa Piega Bandiere Zona Piega Bandiere

      U     "EV327";
      UN    "M7.6";
      U     "T65";
      U     "MG";
      U     "M144.2";
      S     DB96.DBX   68.2;
NETWORK
TITLE =Allarme Avanti Piega Bandiere Zona Piega Bandiere

      U     "EV326";
      UN    "M7.7";
      U     "T65";
      U     "MG";
      U     "M144.2";
      S     DB96.DBX   68.3;
NETWORK
TITLE =Allarme Indietro Piega Bandiere Zona Piega Bandiere

      U     "EV330";
      U(    ;
      O     "M8.0";
      O     "M8.1";
      )     ;
      U     "T65";
      U     "MG";
      U     "M144.2";
      S     DB96.DBX   68.4;
NETWORK
TITLE =Allarme Catena Zona Bandiere

      U     "EV331";
      U(    ;
      ON    "M8.0";
      ON    "M8.1";
      )     ;
      U     "T65";
      U     "MG";
      U     "M144.2";
      S     DB96.DBX   68.5;
NETWORK
TITLE =Allarme Salita Fermo in Uscita Zona Piega Bandiere

      U     "IM16";
      U     "MG";
      =     DB96.DBX   68.6;
NETWORK
TITLE =Allarme Discesa Fermo in Uscita Zona Piega Bandiere

      U     "EV321";
      U     "M7.4";
      U     "T65";
      U     "MG";
      U     "M144.2";
      S     DB96.DBX   68.7;
NETWORK
TITLE =Allarme Salita Fermo in Arrivo Zona Ascensore

      U     "EV320";
      UN    "M7.4";
      U     "T65";
      U     "MG";
      U     "M144.2";
      S     DB96.DBX   69.0;
NETWORK
TITLE =Allarme Discesa Fermo in Arrivo Zona Ascensore

      U     "EV323";
      U     "M7.5";
      U     "T65";
      U     "MG";
      U     "M144.2";
      S     DB96.DBX   69.1;
NETWORK
TITLE =Allarme Salita Fermo Pallet Anteriore Zona Ascensore

      U     "EV322";
      UN    "M7.5";
      U     "T65";
      U     "MG";
      U     "M144.2";
      S     DB96.DBX   69.2;
NETWORK
TITLE =Allarme Discesa Fermo Pallet Anteriore Zona Ascensore

      U     "EV352";
      U     "M54.1";
      U     "T65";
      U     "MG";
      U     "M144.2";
      S     DB96.DBX   69.3;
NETWORK
TITLE =Allarme Salita Fermo Pallet Posteriore Zona Ascensore

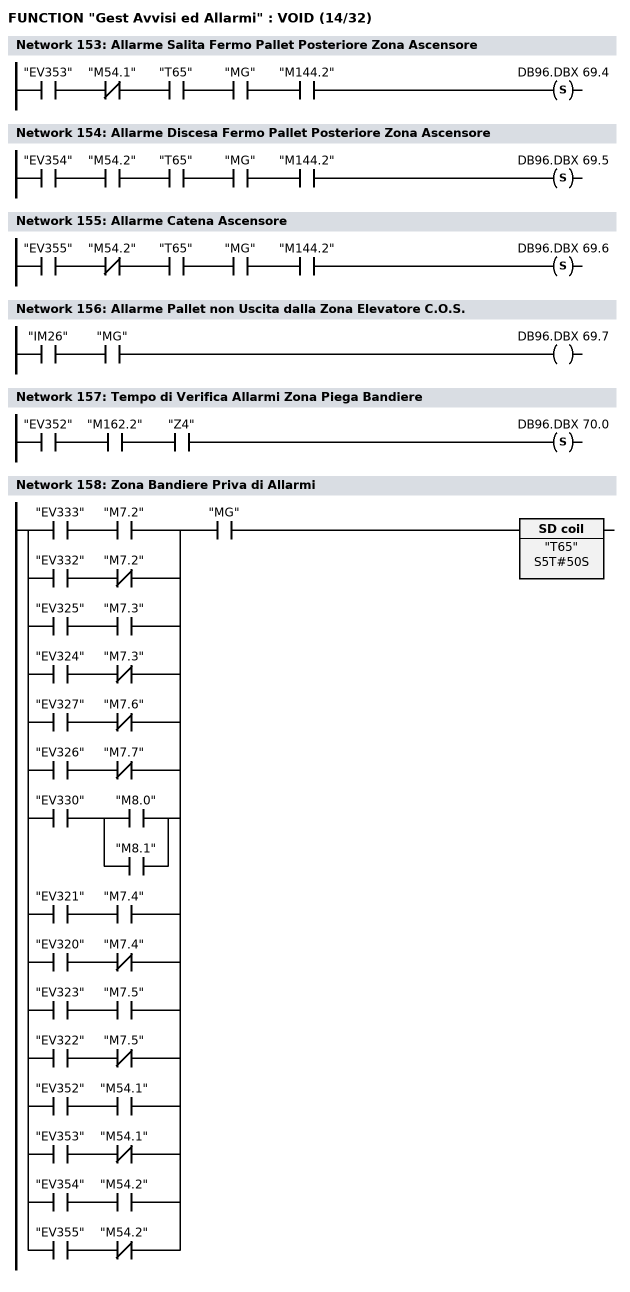
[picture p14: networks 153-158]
      U     "EV353";
      UN    "M54.1";
      U     "T65";
      U     "MG";
      U     "M144.2";
      S     DB96.DBX   69.4;
NETWORK
TITLE =Allarme Discesa Fermo Pallet Posteriore Zona Ascensore

      U     "EV354";
      U     "M54.2";
      U     "T65";
      U     "MG";
      U     "M144.2";
      S     DB96.DBX   69.5;
NETWORK
TITLE =Allarme Catena Ascensore

      U     "EV355";
      UN    "M54.2";
      U     "T65";
      U     "MG";
      U     "M144.2";
      S     DB96.DBX   69.6;
NETWORK
TITLE =Allarme Pallet non Uscita dalla Zona Elevatore C.O.S.

      U     "IM26";
      U     "MG";
      =     DB96.DBX   69.7;
NETWORK
TITLE =Tempo di Verifica Allarmi Zona Piega Bandiere

      U     "EV352";
      U     "M162.2";
      U     "Z4";
      S     DB96.DBX   70.0;
NETWORK
TITLE =Zona Bandiere Priva di Allarmi

      U(    ;
      U     "EV333";
      U     "M7.2";
      O     ;
      U     "EV332";
      UN    "M7.2";
      O     ;
      U     "EV325";
      U     "M7.3";
      O     ;
      U     "EV324";
      UN    "M7.3";
      O     ;
      U     "EV327";
      UN    "M7.6";
      O     ;
      U     "EV326";
      UN    "M7.7";
      O     ;
      U     "EV330";
      U(    ;
      O     "M8.0";
      O     "M8.1";
      )     ;
      O     ;
      U     "EV321";
      U     "M7.4";
      O     ;
      U     "EV320";
      UN    "M7.4";
      O     ;
      U     "EV323";
      U     "M7.5";
      O     ;
      U     "EV322";
      UN    "M7.5";
      O     ;
      U     "EV352";
      U     "M54.1";
      O     ;
      U     "EV353";
      UN    "M54.1";
      O     ;
      U     "EV354";
      U     "M54.2";
      O     ;
      U     "EV355";
      UN    "M54.2";
      )     ;
      U     "MG";
      L     S5T#50S;
      SE    "T65";
      NOP   0;
      NOP   0;
      NOP   0;
      NOP   0;
NETWORK
TITLE ======== Zona Apertura Pallet e Scarico =======

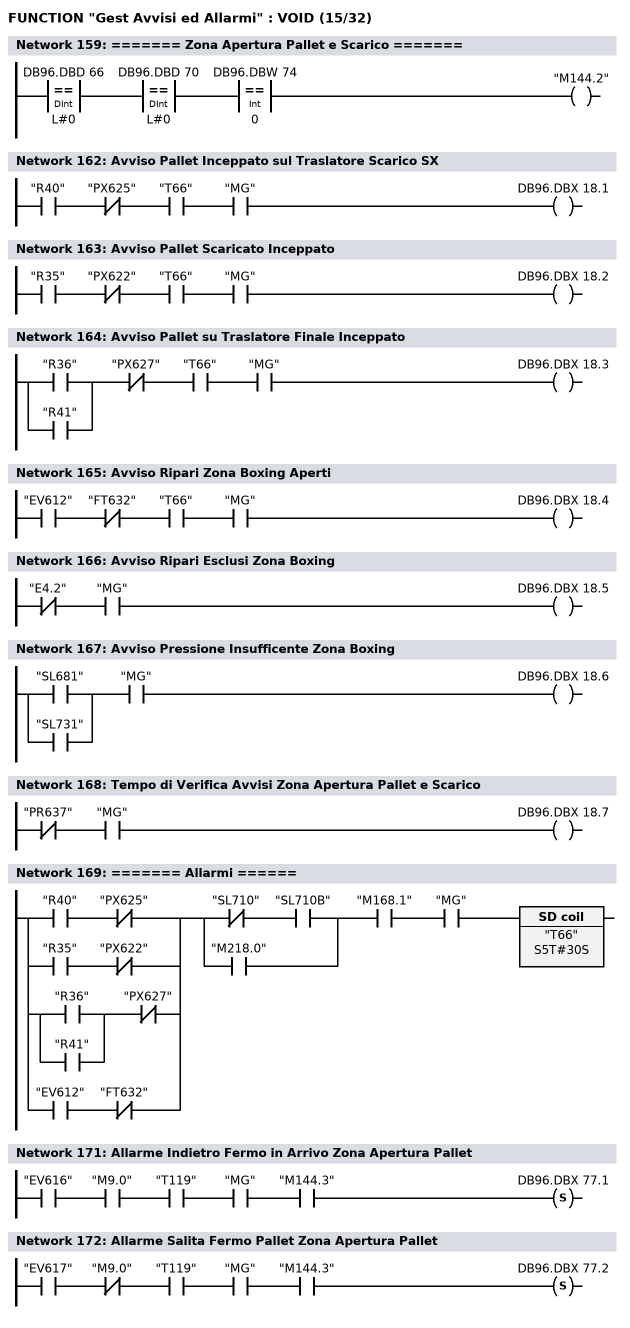
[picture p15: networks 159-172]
      U(    ;
      L     DB96.DBD   66;
      L     L#0;
      ==D   ;
      )     ;
      U(    ;
      L     DB96.DBD   70;
      L     L#0;
      ==D   ;
      )     ;
      U(    ;
      L     DB96.DBW   74;
      L     0;
      ==I   ;
      )     ;
      =     "M144.2";
NETWORK
TITLE ======== Avvisi ======

NETWORK
TITLE =Avviso Pallet Inceppato sul Traslatore Scarico DX

NETWORK
TITLE =Avviso Pallet Inceppato sul Traslatore Scarico SX

      U     "R40";
      UN    "PX625";
      U     "T66";
      U     "MG";
      =     DB96.DBX   18.1;
NETWORK
TITLE =Avviso Pallet Scaricato Inceppato

      U     "R35";
      UN    "PX622";
      U     "T66";
      U     "MG";
      =     DB96.DBX   18.2;
NETWORK
TITLE =Avviso Pallet su Traslatore Finale Inceppato

      U(    ;
      O     "R36";
      O     "R41";
      )     ;
      UN    "PX627";
      U     "T66";
      U     "MG";
      =     DB96.DBX   18.3;
NETWORK
TITLE =Avviso Ripari Zona Boxing Aperti

      U     "EV612";
      UN    "FT632";
      U     "T66";
      U     "MG";
      =     DB96.DBX   18.4;
NETWORK
TITLE =Avviso Ripari Esclusi Zona Boxing

      UN    "E4.2";
      U     "MG";
      =     DB96.DBX   18.5;
NETWORK
TITLE =Avviso Pressione Insufficente Zona Boxing

      U(    ;
      O     "SL681";
      O     "SL731";
      )     ;
      U     "MG";
      =     DB96.DBX   18.6;
NETWORK
TITLE =Tempo di Verifica Avvisi Zona Apertura Pallet e Scarico

      UN    "PR637";
      U     "MG";
      =     DB96.DBX   18.7;
NETWORK
TITLE ======== Allarmi ======

      U(    ;
      U     "R40";
      UN    "PX625";
      O     ;
      U     "R35";
      UN    "PX622";
      O     ;
      U(    ;
      O     "R36";
      O     "R41";
      )     ;
      UN    "PX627";
      O     ;
      U     "EV612";
      UN    "FT632";
      )     ;
      U(    ;
      UN    "SL710";
      U     "SL710B";
      O     "M218.0";
      )     ;
      U     "M168.1";
      U     "MG";
      L     S5T#30S;
      SE    "T66";
      NOP   0;
      NOP   0;
      NOP   0;
      NOP   0;
NETWORK
TITLE =Allarme Avanti Fermo in Arrivo Zona Apertura Pallet

NETWORK
TITLE =Allarme Indietro Fermo in Arrivo Zona Apertura Pallet

      U     "EV616";
      U     "M9.0";
      U     "T119";
      U     "MG";
      U     "M144.3";
      S     DB96.DBX   77.1;
NETWORK
TITLE =Allarme Salita Fermo Pallet Zona Apertura Pallet

      U     "EV617";
      UN    "M9.0";
      U     "T119";
      U     "MG";
      U     "M144.3";
      S     DB96.DBX   77.2;
NETWORK
TITLE =Allarme Discesa Fermo Pallet Zona Apertura Pallet

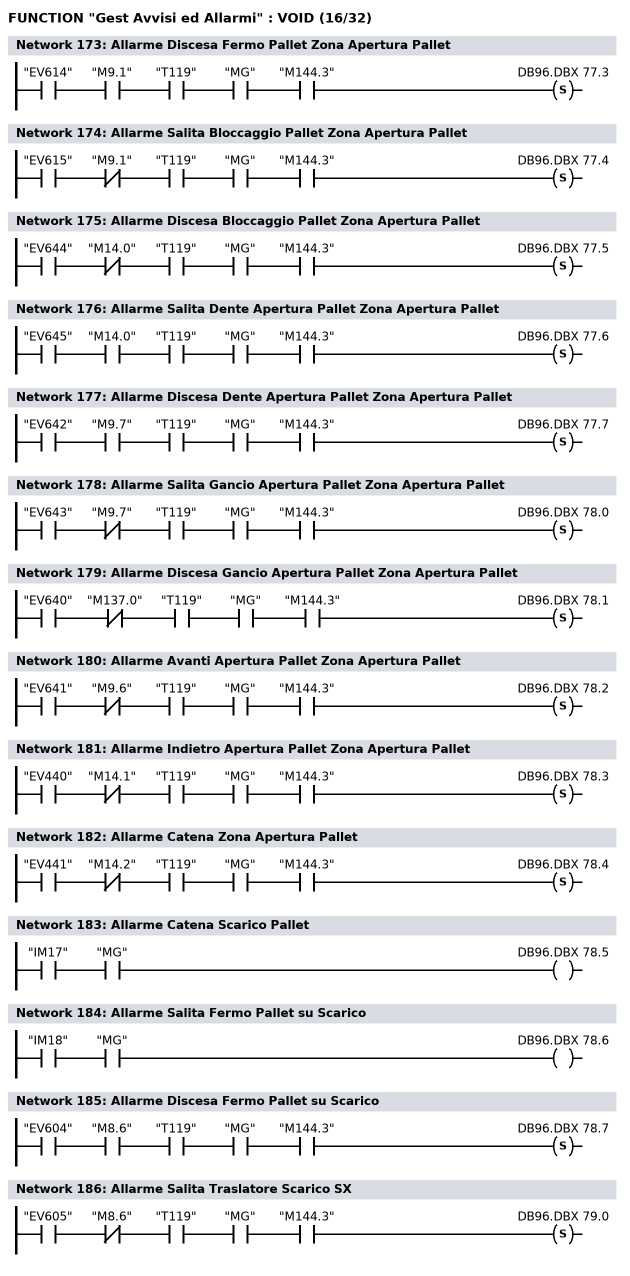
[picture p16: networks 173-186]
      U     "EV614";
      U     "M9.1";
      U     "T119";
      U     "MG";
      U     "M144.3";
      S     DB96.DBX   77.3;
NETWORK
TITLE =Allarme Salita Bloccaggio Pallet Zona Apertura Pallet

      U     "EV615";
      UN    "M9.1";
      U     "T119";
      U     "MG";
      U     "M144.3";
      S     DB96.DBX   77.4;
NETWORK
TITLE =Allarme Discesa Bloccaggio Pallet Zona Apertura Pallet

      U     "EV644";
      UN    "M14.0";
      U     "T119";
      U     "MG";
      U     "M144.3";
      S     DB96.DBX   77.5;
NETWORK
TITLE =Allarme Salita Dente Apertura Pallet Zona Apertura Pallet

      U     "EV645";
      U     "M14.0";
      U     "T119";
      U     "MG";
      U     "M144.3";
      S     DB96.DBX   77.6;
NETWORK
TITLE =Allarme Discesa Dente Apertura Pallet Zona Apertura Pallet

      U     "EV642";
      U     "M9.7";
      U     "T119";
      U     "MG";
      U     "M144.3";
      S     DB96.DBX   77.7;
NETWORK
TITLE =Allarme Salita Gancio Apertura Pallet Zona Apertura Pallet

      U     "EV643";
      UN    "M9.7";
      U     "T119";
      U     "MG";
      U     "M144.3";
      S     DB96.DBX   78.0;
NETWORK
TITLE =Allarme Discesa Gancio Apertura Pallet Zona Apertura Pallet

      U     "EV640";
      UN    "M137.0";
      U     "T119";
      U     "MG";
      U     "M144.3";
      S     DB96.DBX   78.1;
NETWORK
TITLE =Allarme Avanti Apertura Pallet Zona Apertura Pallet

      U     "EV641";
      UN    "M9.6";
      U     "T119";
      U     "MG";
      U     "M144.3";
      S     DB96.DBX   78.2;
NETWORK
TITLE =Allarme Indietro Apertura Pallet Zona Apertura Pallet

      U     "EV440";
      UN    "M14.1";
      U     "T119";
      U     "MG";
      U     "M144.3";
      S     DB96.DBX   78.3;
NETWORK
TITLE =Allarme Catena Zona Apertura Pallet

      U     "EV441";
      UN    "M14.2";
      U     "T119";
      U     "MG";
      U     "M144.3";
      S     DB96.DBX   78.4;
NETWORK
TITLE =Allarme Catena Scarico Pallet

      U     "IM17";
      U     "MG";
      =     DB96.DBX   78.5;
NETWORK
TITLE =Allarme Salita Fermo Pallet su Scarico

      U     "IM18";
      U     "MG";
      =     DB96.DBX   78.6;
NETWORK
TITLE =Allarme Discesa Fermo Pallet su Scarico

      U     "EV604";
      U     "M8.6";
      U     "T119";
      U     "MG";
      U     "M144.3";
      S     DB96.DBX   78.7;
NETWORK
TITLE =Allarme Salita Traslatore Scarico SX

      U     "EV605";
      UN    "M8.6";
      U     "T119";
      U     "MG";
      U     "M144.3";
      S     DB96.DBX   79.0;
NETWORK
TITLE =Allarme Discesa Traslatore Scarico SX

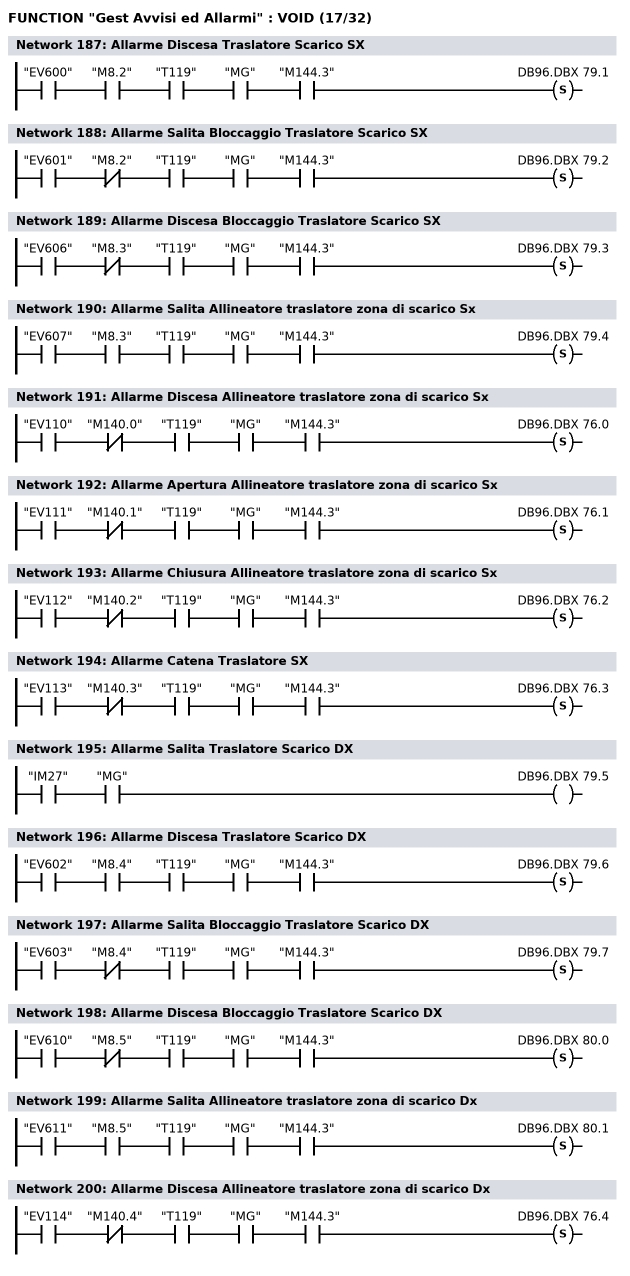
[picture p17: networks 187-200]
      U     "EV600";
      U     "M8.2";
      U     "T119";
      U     "MG";
      U     "M144.3";
      S     DB96.DBX   79.1;
NETWORK
TITLE =Allarme Salita Bloccaggio Traslatore Scarico SX

      U     "EV601";
      UN    "M8.2";
      U     "T119";
      U     "MG";
      U     "M144.3";
      S     DB96.DBX   79.2;
NETWORK
TITLE =Allarme Discesa Bloccaggio Traslatore Scarico SX

      U     "EV606";
      UN    "M8.3";
      U     "T119";
      U     "MG";
      U     "M144.3";
      S     DB96.DBX   79.3;
NETWORK
TITLE =Allarme Salita Allineatore traslatore zona di scarico Sx

      U     "EV607";
      U     "M8.3";
      U     "T119";
      U     "MG";
      U     "M144.3";
      S     DB96.DBX   79.4;
NETWORK
TITLE =Allarme Discesa Allineatore traslatore zona di scarico Sx

      U     "EV110";
      UN    "M140.0";
      U     "T119";
      U     "MG";
      U     "M144.3";
      S     DB96.DBX   76.0;
NETWORK
TITLE =Allarme Apertura Allineatore traslatore zona di scarico Sx

      U     "EV111";
      UN    "M140.1";
      U     "T119";
      U     "MG";
      U     "M144.3";
      S     DB96.DBX   76.1;
NETWORK
TITLE =Allarme Chiusura Allineatore traslatore zona di scarico Sx

      U     "EV112";
      UN    "M140.2";
      U     "T119";
      U     "MG";
      U     "M144.3";
      S     DB96.DBX   76.2;
NETWORK
TITLE =Allarme Catena Traslatore SX

      U     "EV113";
      UN    "M140.3";
      U     "T119";
      U     "MG";
      U     "M144.3";
      S     DB96.DBX   76.3;
NETWORK
TITLE =Allarme Salita Traslatore Scarico DX

      U     "IM27";
      U     "MG";
      =     DB96.DBX   79.5;
NETWORK
TITLE =Allarme Discesa Traslatore Scarico DX

      U     "EV602";
      U     "M8.4";
      U     "T119";
      U     "MG";
      U     "M144.3";
      S     DB96.DBX   79.6;
NETWORK
TITLE =Allarme Salita Bloccaggio Traslatore Scarico DX

      U     "EV603";
      UN    "M8.4";
      U     "T119";
      U     "MG";
      U     "M144.3";
      S     DB96.DBX   79.7;
NETWORK
TITLE =Allarme Discesa Bloccaggio Traslatore Scarico DX

      U     "EV610";
      UN    "M8.5";
      U     "T119";
      U     "MG";
      U     "M144.3";
      S     DB96.DBX   80.0;
NETWORK
TITLE =Allarme Salita Allineatore traslatore zona di scarico Dx

      U     "EV611";
      U     "M8.5";
      U     "T119";
      U     "MG";
      U     "M144.3";
      S     DB96.DBX   80.1;
NETWORK
TITLE =Allarme Discesa Allineatore traslatore zona di scarico Dx

      U     "EV114";
      UN    "M140.4";
      U     "T119";
      U     "MG";
      U     "M144.3";
      S     DB96.DBX   76.4;
NETWORK
TITLE =Allarme Apertura Allineatore traslatore zona di scarico Dx

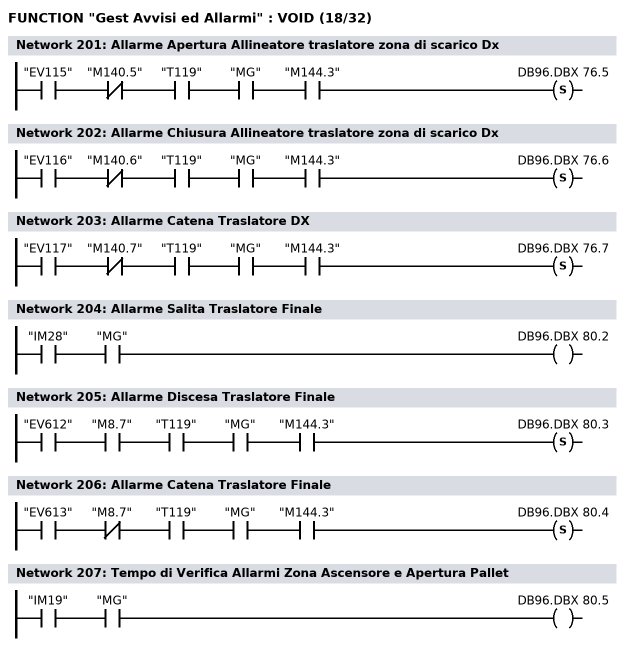
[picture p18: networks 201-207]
      U     "EV115";
      UN    "M140.5";
      U     "T119";
      U     "MG";
      U     "M144.3";
      S     DB96.DBX   76.5;
NETWORK
TITLE =Allarme Chiusura Allineatore traslatore zona di scarico Dx

      U     "EV116";
      UN    "M140.6";
      U     "T119";
      U     "MG";
      U     "M144.3";
      S     DB96.DBX   76.6;
NETWORK
TITLE =Allarme Catena Traslatore DX

      U     "EV117";
      UN    "M140.7";
      U     "T119";
      U     "MG";
      U     "M144.3";
      S     DB96.DBX   76.7;
NETWORK
TITLE =Allarme Salita Traslatore Finale

      U     "IM28";
      U     "MG";
      =     DB96.DBX   80.2;
NETWORK
TITLE =Allarme Discesa Traslatore Finale

      U     "EV612";
      U     "M8.7";
      U     "T119";
      U     "MG";
      U     "M144.3";
      S     DB96.DBX   80.3;
NETWORK
TITLE =Allarme Catena Traslatore Finale

      U     "EV613";
      UN    "M8.7";
      U     "T119";
      U     "MG";
      U     "M144.3";
      S     DB96.DBX   80.4;
NETWORK
TITLE =Tempo di Verifica Allarmi Zona Ascensore e Apertura Pallet

      U     "IM19";
      U     "MG";
      =     DB96.DBX   80.5;
NETWORK
TITLE =Zona Ascensore e Apertura Pallet Priva di Allarmi

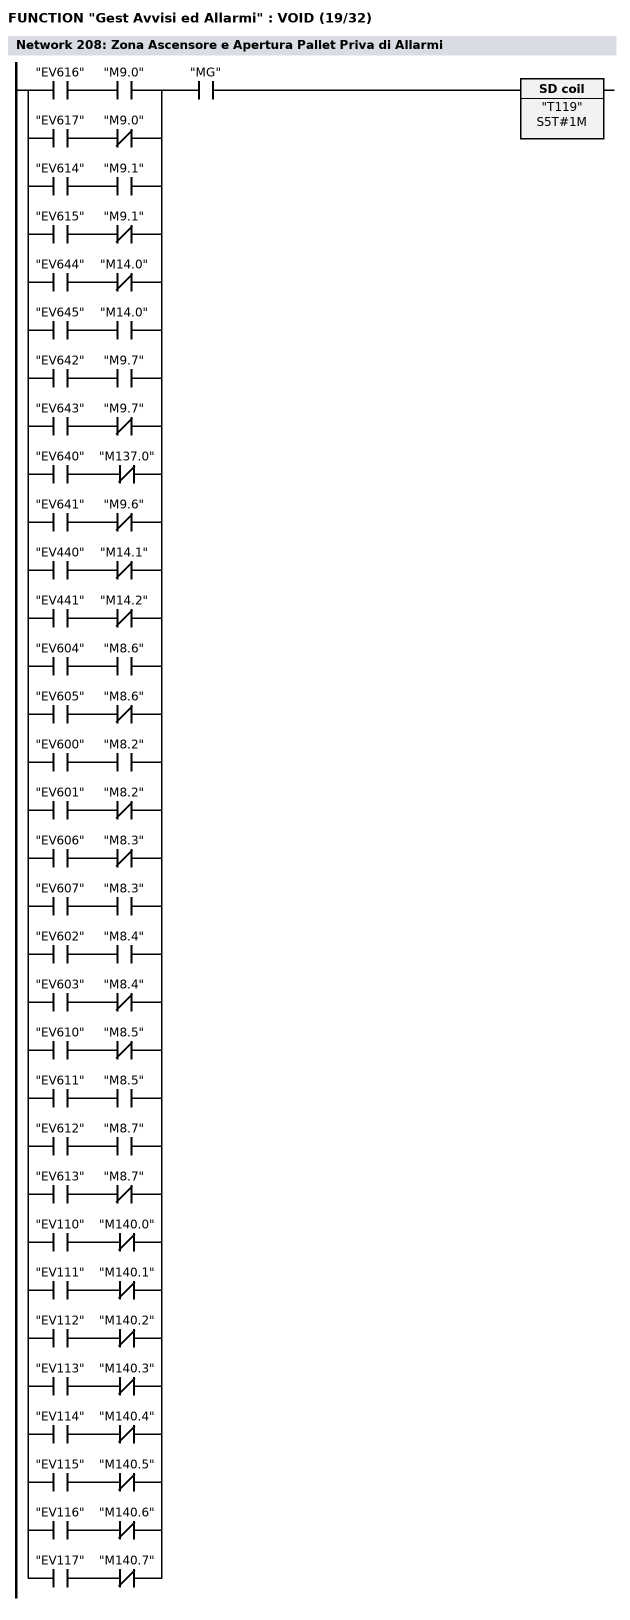
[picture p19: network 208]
      U(    ;
      U     "EV616";
      U     "M9.0";
      O     ;
      U     "EV617";
      UN    "M9.0";
      O     ;
      U     "EV614";
      U     "M9.1";
      O     ;
      U     "EV615";
      UN    "M9.1";
      O     ;
      U     "EV644";
      UN    "M14.0";
      O     ;
      U     "EV645";
      U     "M14.0";
      O     ;
      U     "EV642";
      U     "M9.7";
      O     ;
      U     "EV643";
      UN    "M9.7";
      O     ;
      U     "EV640";
      UN    "M137.0";
      O     ;
      U     "EV641";
      UN    "M9.6";
      O     ;
      U     "EV440";
      UN    "M14.1";
      O     ;
      U     "EV441";
      UN    "M14.2";
      O     ;
      U     "EV604";
      U     "M8.6";
      O     ;
      U     "EV605";
      UN    "M8.6";
      O     ;
      U     "EV600";
      U     "M8.2";
      O     ;
      U     "EV601";
      UN    "M8.2";
      O     ;
      U     "EV606";
      UN    "M8.3";
      O     ;
      U     "EV607";
      U     "M8.3";
      O     ;
      U     "EV602";
      U     "M8.4";
      O     ;
      U     "EV603";
      UN    "M8.4";
      O     ;
      U     "EV610";
      UN    "M8.5";
      O     ;
      U     "EV611";
      U     "M8.5";
      O     ;
      U     "EV612";
      U     "M8.7";
      O     ;
      U     "EV613";
      UN    "M8.7";
      O     ;
      U     "EV110";
      UN    "M140.0";
      O     ;
      U     "EV111";
      UN    "M140.1";
      O     ;
      U     "EV112";
      UN    "M140.2";
      O     ;
      U     "EV113";
      UN    "M140.3";
      O     ;
      U     "EV114";
      UN    "M140.4";
      O     ;
      U     "EV115";
      UN    "M140.5";
      O     ;
      U     "EV116";
      UN    "M140.6";
      O     ;
      U     "EV117";
      UN    "M140.7";
      )     ;
      U     "MG";
      L     S5T#1M;
      SE    "T119";
      NOP   0;
      NOP   0;
      NOP   0;
      NOP   0;
NETWORK
TITLE ======== Zona Boxing SX =======

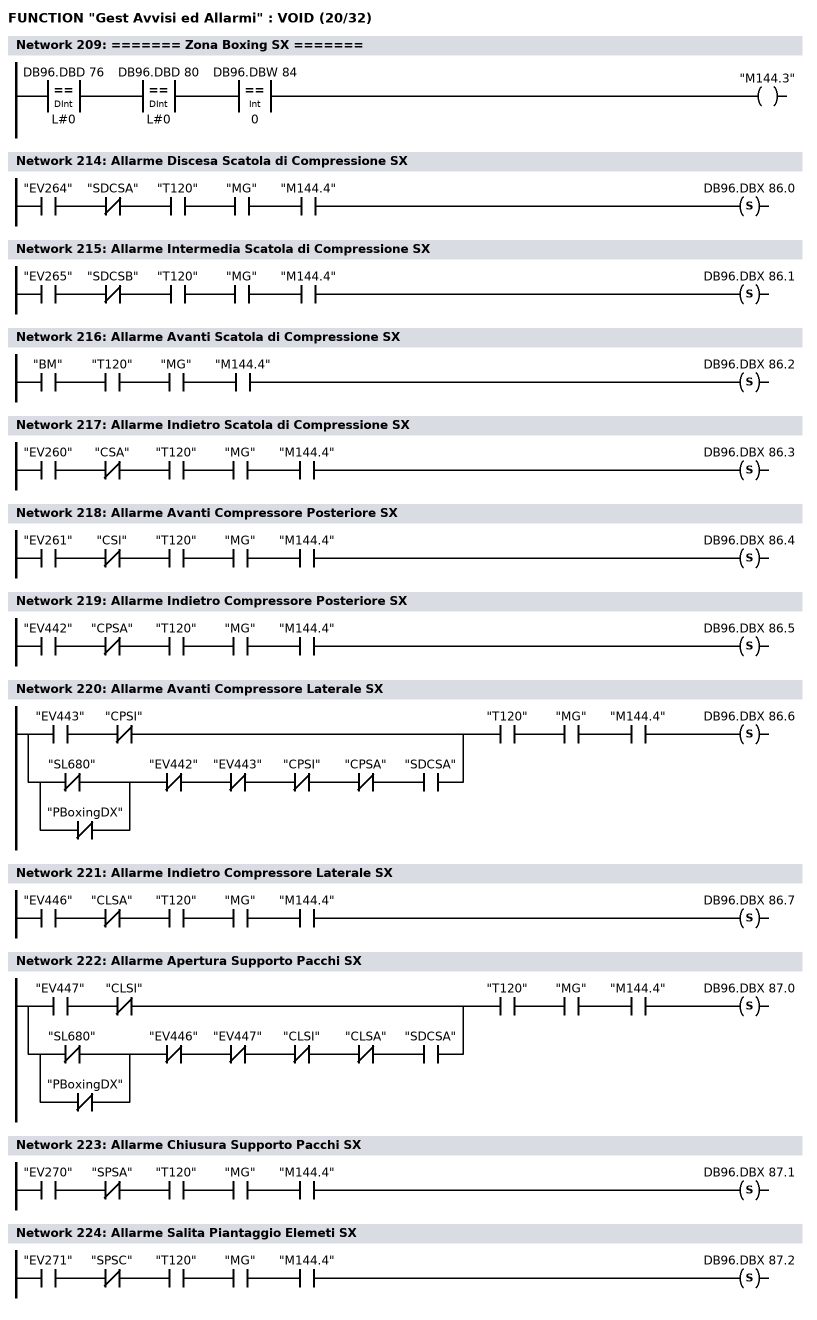
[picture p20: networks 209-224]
      U(    ;
      L     DB96.DBD   76;
      L     L#0;
      ==D   ;
      )     ;
      U(    ;
      L     DB96.DBD   80;
      L     L#0;
      ==D   ;
      )     ;
      U(    ;
      L     DB96.DBW   84;
      L     0;
      ==I   ;
      )     ;
      =     "M144.3";
NETWORK
TITLE ======== Avvisi ======

NETWORK
TITLE =Tempo di Verifica Avvisi Zona Boxing SX

NETWORK
TITLE ======== Allarmi ======

NETWORK
TITLE =Allarme Salita Scatola di Compressione SX

NETWORK
TITLE =Allarme Discesa Scatola di Compressione SX

      U     "EV264";
      UN    "SDCSA";
      U     "T120";
      U     "MG";
      U     "M144.4";
      S     DB96.DBX   86.0;
NETWORK
TITLE =Allarme Intermedia Scatola di Compressione SX

      U     "EV265";
      UN    "SDCSB";
      U     "T120";
      U     "MG";
      U     "M144.4";
      S     DB96.DBX   86.1;
NETWORK
TITLE =Allarme Avanti Scatola di Compressione SX

      U     "BM";
      U     "T120";
      U     "MG";
      U     "M144.4";
      S     DB96.DBX   86.2;
NETWORK
TITLE =Allarme Indietro Scatola di Compressione SX

      U     "EV260";
      UN    "CSA";
      U     "T120";
      U     "MG";
      U     "M144.4";
      S     DB96.DBX   86.3;
NETWORK
TITLE =Allarme Avanti Compressore Posteriore SX

      U     "EV261";
      UN    "CSI";
      U     "T120";
      U     "MG";
      U     "M144.4";
      S     DB96.DBX   86.4;
NETWORK
TITLE =Allarme Indietro Compressore Posteriore SX

      U     "EV442";
      UN    "CPSA";
      U     "T120";
      U     "MG";
      U     "M144.4";
      S     DB96.DBX   86.5;
NETWORK
TITLE =Allarme Avanti Compressore Laterale SX

      U(    ;
      U     "EV443";
      UN    "CPSI";
      O     ;
      U(    ;
      ON    "SL680";
      ON    "PBoxingDX";
      )     ;
      UN    "EV442";
      UN    "EV443";
      UN    "CPSI";
      UN    "CPSA";
      U     "SDCSA";
      )     ;
      U     "T120";
      U     "MG";
      U     "M144.4";
      S     DB96.DBX   86.6;
NETWORK
TITLE =Allarme Indietro Compressore Laterale SX

      U     "EV446";
      UN    "CLSA";
      U     "T120";
      U     "MG";
      U     "M144.4";
      S     DB96.DBX   86.7;
NETWORK
TITLE =Allarme Apertura Supporto Pacchi SX

      U(    ;
      U     "EV447";
      UN    "CLSI";
      O     ;
      U(    ;
      ON    "SL680";
      ON    "PBoxingDX";
      )     ;
      UN    "EV446";
      UN    "EV447";
      UN    "CLSI";
      UN    "CLSA";
      U     "SDCSA";
      )     ;
      U     "T120";
      U     "MG";
      U     "M144.4";
      S     DB96.DBX   87.0;
NETWORK
TITLE =Allarme Chiusura Supporto Pacchi SX

      U     "EV270";
      UN    "SPSA";
      U     "T120";
      U     "MG";
      U     "M144.4";
      S     DB96.DBX   87.1;
NETWORK
TITLE =Allarme Salita Piantaggio Elemeti SX

      U     "EV271";
      UN    "SPSC";
      U     "T120";
      U     "MG";
      U     "M144.4";
      S     DB96.DBX   87.2;
NETWORK
TITLE =Allarme Discesa Piantaggio Elemeti SX

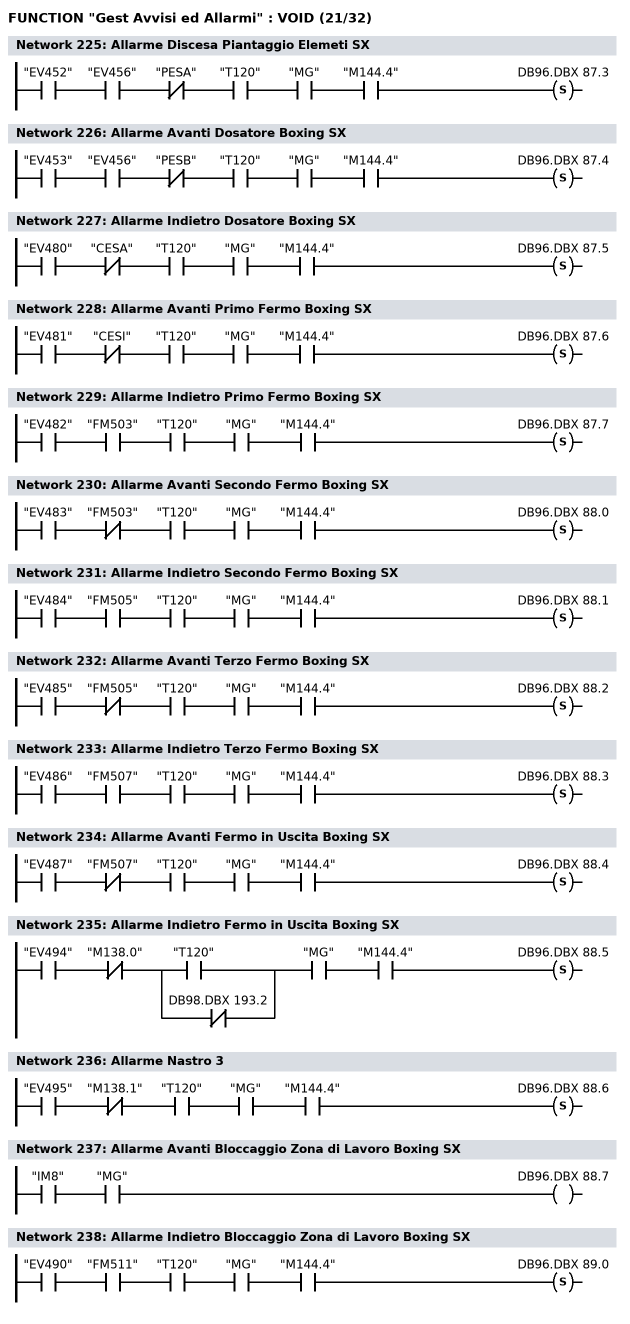
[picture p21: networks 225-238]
      U     "EV452";
      U     "EV456";
      UN    "PESA";
      U     "T120";
      U     "MG";
      U     "M144.4";
      S     DB96.DBX   87.3;
NETWORK
TITLE =Allarme Avanti Dosatore Boxing SX

      U     "EV453";
      U     "EV456";
      UN    "PESB";
      U     "T120";
      U     "MG";
      U     "M144.4";
      S     DB96.DBX   87.4;
NETWORK
TITLE =Allarme Indietro Dosatore Boxing SX

      U     "EV480";
      UN    "CESA";
      U     "T120";
      U     "MG";
      U     "M144.4";
      S     DB96.DBX   87.5;
NETWORK
TITLE =Allarme Avanti Primo Fermo Boxing SX

      U     "EV481";
      UN    "CESI";
      U     "T120";
      U     "MG";
      U     "M144.4";
      S     DB96.DBX   87.6;
NETWORK
TITLE =Allarme Indietro Primo Fermo Boxing SX

      U     "EV482";
      U     "FM503";
      U     "T120";
      U     "MG";
      U     "M144.4";
      S     DB96.DBX   87.7;
NETWORK
TITLE =Allarme Avanti Secondo Fermo Boxing SX

      U     "EV483";
      UN    "FM503";
      U     "T120";
      U     "MG";
      U     "M144.4";
      S     DB96.DBX   88.0;
NETWORK
TITLE =Allarme Indietro Secondo Fermo Boxing SX

      U     "EV484";
      U     "FM505";
      U     "T120";
      U     "MG";
      U     "M144.4";
      S     DB96.DBX   88.1;
NETWORK
TITLE =Allarme Avanti Terzo Fermo Boxing SX

      U     "EV485";
      UN    "FM505";
      U     "T120";
      U     "MG";
      U     "M144.4";
      S     DB96.DBX   88.2;
NETWORK
TITLE =Allarme Indietro Terzo Fermo Boxing SX

      U     "EV486";
      U     "FM507";
      U     "T120";
      U     "MG";
      U     "M144.4";
      S     DB96.DBX   88.3;
NETWORK
TITLE =Allarme Avanti Fermo in Uscita Boxing SX

      U     "EV487";
      UN    "FM507";
      U     "T120";
      U     "MG";
      U     "M144.4";
      S     DB96.DBX   88.4;
NETWORK
TITLE =Allarme Indietro Fermo in Uscita Boxing SX

      U     "EV494";
      UN    "M138.0";
      U(    ;
      O     "T120";
      ON    DB98.DBX  193.2;
      )     ;
      U     "MG";
      U     "M144.4";
      S     DB96.DBX   88.5;
NETWORK
TITLE =Allarme Nastro 3

      U     "EV495";
      UN    "M138.1";
      U     "T120";
      U     "MG";
      U     "M144.4";
      S     DB96.DBX   88.6;
NETWORK
TITLE =Allarme Avanti Bloccaggio Zona di Lavoro Boxing SX

      U     "IM8";
      U     "MG";
      =     DB96.DBX   88.7;
NETWORK
TITLE =Allarme Indietro Bloccaggio Zona di Lavoro Boxing SX

      U     "EV490";
      U     "FM511";
      U     "T120";
      U     "MG";
      U     "M144.4";
      S     DB96.DBX   89.0;
NETWORK
TITLE =Tempo di Verifica Allarmi Zona Boxing SX

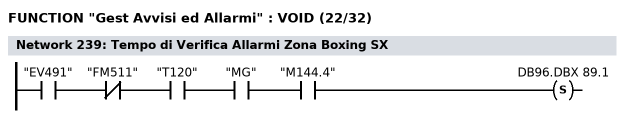
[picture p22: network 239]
      U     "EV491";
      UN    "FM511";
      U     "T120";
      U     "MG";
      U     "M144.4";
      S     DB96.DBX   89.1;
NETWORK
TITLE =Zona Boxing SX Priva di Allarmi

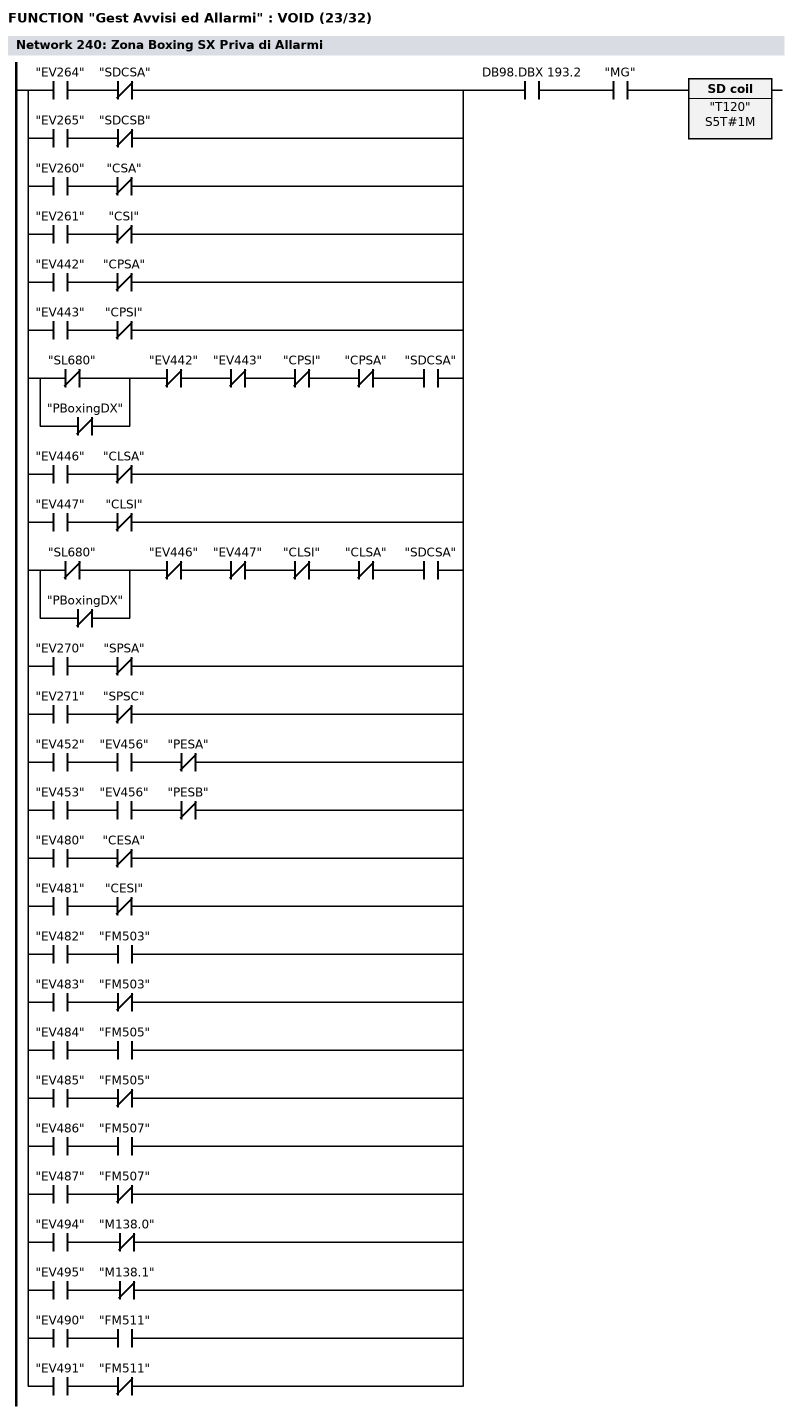
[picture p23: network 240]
      U(    ;
      U     "EV264";
      UN    "SDCSA";
      O     ;
      U     "EV265";
      UN    "SDCSB";
      O     ;
      U     "EV260";
      UN    "CSA";
      O     ;
      U     "EV261";
      UN    "CSI";
      O     ;
      U     "EV442";
      UN    "CPSA";
      O     ;
      U     "EV443";
      UN    "CPSI";
      O     ;
      U(    ;
      ON    "SL680";
      ON    "PBoxingDX";
      )     ;
      UN    "EV442";
      UN    "EV443";
      UN    "CPSI";
      UN    "CPSA";
      U     "SDCSA";
      O     ;
      U     "EV446";
      UN    "CLSA";
      O     ;
      U     "EV447";
      UN    "CLSI";
      O     ;
      U(    ;
      ON    "SL680";
      ON    "PBoxingDX";
      )     ;
      UN    "EV446";
      UN    "EV447";
      UN    "CLSI";
      UN    "CLSA";
      U     "SDCSA";
      O     ;
      U     "EV270";
      UN    "SPSA";
      O     ;
      U     "EV271";
      UN    "SPSC";
      O     ;
      U     "EV452";
      U     "EV456";
      UN    "PESA";
      O     ;
      U     "EV453";
      U     "EV456";
      UN    "PESB";
      O     ;
      U     "EV480";
      UN    "CESA";
      O     ;
      U     "EV481";
      UN    "CESI";
      O     ;
      U     "EV482";
      U     "FM503";
      O     ;
      U     "EV483";
      UN    "FM503";
      O     ;
      U     "EV484";
      U     "FM505";
      O     ;
      U     "EV485";
      UN    "FM505";
      O     ;
      U     "EV486";
      U     "FM507";
      O     ;
      U     "EV487";
      UN    "FM507";
      O     ;
      U     "EV494";
      UN    "M138.0";
      O     ;
      U     "EV495";
      UN    "M138.1";
      O     ;
      U     "EV490";
      U     "FM511";
      O     ;
      U     "EV491";
      UN    "FM511";
      )     ;
      U     DB98.DBX  193.2;
      U     "MG";
      L     S5T#1M;
      SE    "T120";
      NOP   0;
      NOP   0;
      NOP   0;
      NOP   0;
NETWORK
TITLE ======== Zona Boxing DX =======

      U(    ;
      L     DB96.DBD   86;
      L     L#0;
      ==D   ;
      )     ;
      U(    ;
      L     DB96.DBD   90;
      L     L#0;
      ==D   ;
      )     ;
      U(    ;
      L     DB96.DBW   94;
      L     0;
      ==I   ;
      )     ;
      =     "M144.4";
NETWORK
TITLE ======== Avvisi ======

NETWORK
TITLE =Tempo di Verifica Avvisi Zona Boxing DX

NETWORK
TITLE ======== Allarmi ======

NETWORK
TITLE =Allarme Salita Scatola di Compressione DX

NETWORK
TITLE =Allarme Discesa Scatola di Compressione DX

      U     "EV266";
      UN    "SDCDA";
      U     "T121";
      U     "MG";
      U     "M144.5";
      S     DB96.DBX   96.0;
NETWORK
TITLE =Allarme Intermedia Scatola di Compressione DX

      U     "EV267";
      UN    "SDCDB";
      U     "T121";
      U     "MG";
      U     "M144.5";
      S     DB96.DBX   96.1;
NETWORK
TITLE =Allarme Avanti Scatola di Compressione DX

      U     "BM";
      U     "T121";
      U     "MG";
      U     "M144.5";
      S     DB96.DBX   96.2;
NETWORK
TITLE =Allarme Indietro Scatola di Compressione DX

      U     "EV262";
      UN    "CDA";
      U     "T121";
      U     "MG";
      U     "M144.5";
      S     DB96.DBX   96.3;
NETWORK
TITLE =Allarme Avanti Compressore Posteriore DX

      U     "EV263";
      UN    "CDI";
      U     "T121";
      U     "MG";
      U     "M144.5";
      S     DB96.DBX   96.4;
NETWORK
TITLE =Allarme Indietro Compressore Posteriore DX

      U     "EV450";
      UN    "CPDA";
      U     "T121";
      U     "MG";
      U     "M144.5";
      S     DB96.DBX   96.5;
NETWORK
TITLE =Allarme Avanti Compressore Laterale DX

      U(    ;
      U     "EV451";
      UN    "CPDI";
      O     ;
      U(    ;
      ON    "SL680";
      ON    "PBoxingDX";
      )     ;
      UN    "EV450";
      UN    "EV451";
      UN    "CPDA";
      UN    "CPDI";
      U     "SDCDA";
      )     ;
      U     "T121";
      U     "MG";
      U     "M144.5";
      S     DB96.DBX   96.6;
NETWORK
TITLE =Allarme Indietro Compressore Laterale DX

      U     "EV444";
      UN    "CLDA";
      U     "T121";
      U     "MG";
      U     "M144.5";
      S     DB96.DBX   96.7;
NETWORK
TITLE =Allarme Apertura Supporto Pacchi DX

      U(    ;
      U     "EV445";
      UN    "CLDI";
      O     ;
      U(    ;
      ON    "SL680";
      ON    "PBoxingDX";
      )     ;
      UN    "EV444";
      UN    "EV445";
      UN    "CLDA";
      UN    "CLDI";
      U     "SDCDA";
      )     ;
      U     "T121";
      U     "MG";
      U     "M144.5";
      S     DB96.DBX   97.0;
NETWORK
TITLE =Allarme Chiusura Supporto Pacchi DX

      U     "EV272";
      UN    "SPDA";
      U     "T121";
      U     "MG";
      U     "M144.5";
      S     DB96.DBX   97.1;
NETWORK
TITLE =Allarme Salita Piantaggio Elemeti DX

      U     "EV273";
      UN    "SPDC";
      U     "T121";
      U     "MG";
      U     "M144.5";
      S     DB96.DBX   97.2;
NETWORK
TITLE =Allarme Discesa Piantaggio Elemeti DX

      U     "EV454";
      U     "EV456";
      UN    "PEDA";
      U     "T121";
      U     "MG";
      U     "M144.5";
      S     DB96.DBX   97.3;
NETWORK
TITLE =Allarme Avanti Dosatore Boxing DX

      U     "EV455";
      U     "EV456";
      UN    "PEDB";
      U     "T121";
      U     "MG";
      U     "M144.5";
      S     DB96.DBX   97.4;
NETWORK
TITLE =Allarme Indietro Dosatore Boxing DX

      U     "EV540";
      UN    "CEDA";
      U     "T121";
      U     "MG";
      U     "M144.5";
      S     DB96.DBX   97.5;
NETWORK
TITLE =Allarme Avanti Primo Fermo Boxing DX

      U     "EV541";
      UN    "CEDI";
      U     "T121";
      U     "MG";
      U     "M144.5";
      S     DB96.DBX   97.6;
NETWORK
TITLE =Allarme Indietro Primo Fermo Boxing DX

      U     "EV542";
      U     "FM563";
      U     "T121";
      U     "MG";
      U     "M144.5";
      S     DB96.DBX   97.7;
NETWORK
TITLE =Allarme Avanti Secondo Fermo Boxing DX

      U     "EV543";
      U     A     55.3;
      UN    "FM563";
      U     "T121";
      U     "MG";
      U     "M144.5";
      S     DB96.DBX   98.0;
NETWORK
TITLE =Allarme Indietro Secondo Fermo Boxing DX

      U     "EV544";
      U     E     57.5;
      U     "T121";
      U     "MG";
      U     "M144.5";
      S     DB96.DBX   98.1;
NETWORK
TITLE =Allarme Avanti Terzo Fermo Boxing DX

      U     "EV545";
      UN    E     57.5;
      U     "T121";
      U     "MG";
      U     "M144.5";
      S     DB96.DBX   98.2;
NETWORK
TITLE =Allarme Indietro Terzo Fermo Boxing DX

      U     "EV546";
      U     "FM567";
      U     "T121";
      U     "MG";
      U     "M144.5";
      S     DB96.DBX   98.3;
NETWORK
TITLE =Allarme Avanti Bloccaggio Zona di Lavoro Boxing DX

      U     "EV547";
      UN    "FM567";
      U     "T121";
      U     "MG";
      U     "M144.5";
      S     DB96.DBX   98.4;
NETWORK
TITLE =Allarme Indietro Bloccaggio Zona di Lavoro Boxing DX

      U     "EV550";
      U     "FM571";
      U     "T121";
      U     "MG";
      U     "M144.5";
      S     DB96.DBX   98.5;
NETWORK
TITLE =Allarme Nastro 1

      U     "EV551";
      UN    "FM571";
      U     "T121";
      U     "MG";
      U     "M144.5";
      S     DB96.DBX   98.6;
NETWORK
TITLE =Allarme Avanti Spintore da Nastro 1 a Nastro 2

      U     "IM6";
      U     "MG";
      =     DB96.DBX   98.7;
NETWORK
TITLE =Allarme Indietro Spintore da Nastro 1 a Nastro 2

      U     "EV492";
      UN    "BDSN1N2A";
      U     "T121";
      U     "MG";
      U     "M144.5";
      S     DB96.DBX   99.0;
NETWORK
TITLE =Allarme Avanti Barra Spinta da Nastro 2 a Nastro 3

      U     "EV493";
      UN    "BDSN1N2I";
      U     "T121";
      U     "MG";
      U     "M144.5";
      S     DB96.DBX   99.1;
NETWORK
TITLE =Allarme Indietro Barra Spinta da Nastro 2 a Nastro 3

      U     "EV496";
      UN    "BADSSN3A";
      U     "T121";
      U     "MG";
      U     "M144.5";
      S     DB96.DBX   99.2;
NETWORK
TITLE =Allarme Avanti Braccio di Spostamento da Nastro 2 a Nastro 3

      U     "EV497";
      UN    "BADSSN3I";
      U     "T121";
      U     "MG";
      U     "M144.5";
      S     DB96.DBX   99.3;
NETWORK
TITLE =Allarme Indietro Braccio di Spostamento da Nastro 2 a Nastro 3

      U     "EV520";
      UN    "BDSN2N3A";
      U     "T121";
      U     "MG";
      U     "M144.5";
      S     DB96.DBX   99.4;
NETWORK
TITLE =Allarme Nastro 2

      U     "EV521";
      UN    "BDSN2N3I";
      U(    ;
      O     "T121";
      ON    DB98.DBX  193.1;
      )     ;
      U     "MG";
      U     "M144.5";
      S     DB96.DBX   99.5;
NETWORK
TITLE =Tempo di Verifica Allarmi Zona Boxing DX

      U     "IM7";
      U     "MG";
      =     DB96.DBX   99.6;
NETWORK
TITLE =Zona Boxing DX Priva di Allarmi

      U(    ;
      U     "EV266";
      UN    "SDCDA";
      O     ;
      U     "EV267";
      UN    "SDCDB";
      O     ;
      U     "EV262";
      UN    "CDA";
      O     ;
      U     "EV263";
      UN    "CDI";
      O     ;
      U     "EV450";
      UN    "CPDA";
      O     ;
      U     "EV451";
      UN    "CPDI";
      O     ;
      U(    ;
      ON    "SL680";
      ON    "PBoxingDX";
      )     ;
      UN    "EV450";
      UN    "EV451";
      UN    "CPDA";
      UN    "CPDI";
      U     "SDCDA";
      U     "M58.1";
      O     ;
      U     "EV444";
      UN    "CLDA";
      O     ;
      U     "EV445";
      UN    "CLDI";
      O     ;
      U(    ;
      ON    "SL680";
      ON    "PBoxingDX";
      )     ;
      UN    "EV444";
      UN    "EV445";
      UN    "CLDA";
      UN    "CLDI";
      U     "SDCDA";
      U     "M58.1";
      O     ;
      U     "EV272";
      UN    "SPDA";
      O     ;
      U     "EV273";
      UN    "SPDC";
      O     ;
      U     "EV454";
      U     "EV456";
      UN    "PEDA";
      O     ;
      U     "EV455";
      U     "EV456";
      UN    "PEDB";
      O     ;
      U     "EV540";
      UN    "CEDA";
      O     ;
      U     "EV541";
      UN    "CEDI";
      O     ;
      U     "EV542";
      U     "FM563";
      O     ;
      U     "EV543";
      U     A     55.3;
      UN    "FM563";
      O     ;
      U     "EV544";
      U     E     57.5;
      O     ;
      U     "EV545";
      UN    E     57.5;
      O     ;
      U     "EV546";
      U     "FM567";
      O     ;
      U     "EV547";
      UN    "FM567";
      O     ;
      U     "EV550";
      U     "FM571";
      O     ;
      U     "EV551";
      UN    "FM571";
      O     ;
      U     "EV492";
      UN    "BDSN1N2A";
      O     ;
      U     "EV493";
      UN    "BDSN1N2I";
      O     ;
      U     "EV496";
      UN    "BADSSN3A";
      O     ;
      U     "EV497";
      UN    "BADSSN3I";
      O     ;
      U     "EV520";
      UN    "BDSN2N3A";
      O     ;
      U     "EV521";
      UN    "BDSN2N3I";
      )     ;
      U     DB98.DBX  193.1;
      U     "MG";
      L     S5T#1M;
      SE    "T121";
      NOP   0;
      NOP   0;
      NOP   0;
      NOP   0;
NETWORK
TITLE ======== Varie =======

      U(    ;
      L     DB96.DBD   96;
      L     L#0;
      ==D   ;
      )     ;
      U(    ;
      L     DB96.DBD  100;
      L     L#0;
      ==D   ;
      )     ;
      U(    ;
      L     DB96.DBW  104;
      L     0;
      ==I   ;
      )     ;
      =     "M144.5";
NETWORK
TITLE ======== Avvisi ======

NETWORK
TITLE =Avviso Emergenza Attiva

NETWORK
TITLE =Avviso Asse X Approcciato il FC Softaware +

      UN    "MG";
      =     DB96.DBX   36.0;
NETWORK
TITLE =Avviso Asse X Approcciato il FC Softaware -

      U     DB101.DBX   33.7;
      U     "MG";
      =     DB96.DBX   37.1;
NETWORK
TITLE =Avviso Asse Y Approcciato il FC Softaware +

      U     DB101.DBX   33.6;
      U     "MG";
      =     DB96.DBX   37.2;
NETWORK
TITLE =Avviso Asse Y Approcciato il FC Softaware -

      U     DB102.DBX   33.7;
      U     "MG";
      =     DB96.DBX   37.3;
NETWORK
TITLE =Avviso Asse Z Approcciato il FC Softaware +

      U     DB102.DBX   33.6;
      U     "MG";
      =     DB96.DBX   37.4;
NETWORK
TITLE =Avviso Asse Z Approcciato il FC Softaware -

      U     DB103.DBX   33.7;
      U     "MG";
      =     DB96.DBX   37.5;
NETWORK
TITLE =Avviso Asse B Approcciato il FC Softaware +

      U     DB103.DBX   33.6;
      U     "MG";
      =     DB96.DBX   37.6;
NETWORK
TITLE =Avviso Asse B Approcciato il FC Softaware -

      U     DB104.DBX   33.7;
      U     "MG";
      =     DB96.DBX   37.7;
NETWORK
TITLE =Avviso Svuotamento Zona Boxing Inserito

      U     DB104.DBX   33.6;
      U     "MG";
      =     DB96.DBX   38.0;
NETWORK
TITLE =Avviso Svuotamento Linea Inserito

      U     "M58.7";
      U     "MG";
      =     DB96.DBX   38.3;
NETWORK
TITLE =Avviso Carico C.O.S. Escluso

      U     "M59.0";
      U     "MG";
      =     DB96.DBX   38.4;
NETWORK
TITLE ======== Allarmi ======

      U     DB116.DBX   19.1;
      U     "MG";
      =     DB96.DBX   38.5;
NETWORK
TITLE =Allarme Alimentazione 220Vac

NETWORK
TITLE =Allarme Alimentazione 110Vac

      UN    "IA1";
      U     "MG";
      S     DB96.DBX  106.0;
NETWORK
TITLE =Allarme Alimentazione Input

      UN    "IA7-8";
      U     "MG";
      S     DB96.DBX  106.1;
NETWORK
TITLE =Allarme Alimentazione Output

      UN    "E0.4";
      U     "MG";
      S     DB96.DBX  106.2;
NETWORK
TITLE =Allarme Azionamenti

      UN    "E0.5";
      U     "MG";
      S     DB96.DBX  106.3;
NETWORK
TITLE =Allarme Termica IM4 Scorta

      UN    "OK-AZ";
      U     "MG";
      S     DB96.DBX  106.4;
NETWORK
TITLE =Allarme Centralina Idraulica Generale

      U     "IM4";
      U     "MG";
      S     DB96.DBX  106.5;
NETWORK
TITLE =Allarme Filtro Centralina Idraulica Generale Intasato

      U     "IM5";
      U     "MG";
      S     DB96.DBX  106.6;
NETWORK
TITLE =Allarme Livello Olio Centralina Idraulica Generale Basso

      U     "CP460";
      U     "MG";
      S     DB96.DBX  106.7;
NETWORK
TITLE =Allarme Asse X in Extracorsa +

      U     "GL461";
      U     "MG";
      S     DB96.DBX  107.0;
NETWORK
TITLE =Allarme Asse X in Extracorsa -

      U     "M102.6";
      U     "MG";
      S     DB96.DBX  107.1;
NETWORK
TITLE =Allarme Asse Y in Extracorsa +

      U     "M102.5";
      U     "MG";
      S     DB96.DBX  107.2;
NETWORK
TITLE =Allarme Asse Y in Extracorsa -

      U     "M103.1";
      U     "MG";
      S     DB96.DBX  107.3;
NETWORK
TITLE =Allarme Asse Z in Extracorsa +

      U     "M102.7";
      U     "MG";
      S     DB96.DBX  107.4;
NETWORK
TITLE =Allarme Asse Z in Extracorsa -

      U     "M103.3";
      U     "MG";
      S     DB96.DBX  107.5;
NETWORK
TITLE =Allarme Apertura Pinza Opera di Presa

      U     "M103.2";
      U     "MG";
      S     DB96.DBX  107.6;
NETWORK
TITLE =Allarme Chiusura Pinza Opera di Presa

      U     "EV124";
      UN    "PA";
      U     T    122;
      U     "MG";
      U     "M144.6";
      S     DB96.DBX  107.7;
NETWORK
TITLE =Allarme Traslazione Pinze Polso Avanti

      U     "EV125";
      UN    "PC";
      U     T    122;
      U     "MG";
      U     "M144.6";
      S     DB96.DBX  108.0;
NETWORK
TITLE =Allarme Traslazione Pinze Polso Indietro

      U     "EV100";
      UN    "RPA";
      U     T    122;
      U     "MG";
      U     "M144.6";
      S     DB96.DBX  108.1;
NETWORK
TITLE =Allarme Asse B in Extracorsa +

      U     "EV101";
      UN    "M103.7";
      U     T    122;
      U     "MG";
      U     "M144.6";
      S     DB96.DBX  108.2;
NETWORK
TITLE =Allarme Asse B in Extracorsa -

      U     "M103.5";
      U     "MG";
      S     DB96.DBX  108.3;
NETWORK
TITLE =Anomalia Asse X Robot Boxing

      U     "M103.4";
      U     "MG";
      S     DB96.DBX  108.4;
NETWORK
TITLE =Anomalia Asse Y Robot Boxing

      U     "M201.4";
      U     "MG";
      UN    DB101.DBX   33.6;
      UN    DB101.DBX   33.7;
      S     DB96.DBX  109.5;
NETWORK
TITLE =Anomalia Asse Z Robot Boxing

      U     "M206.4";
      U     "MG";
      UN    DB102.DBX   33.6;
      UN    DB102.DBX   33.7;
      S     DB96.DBX  109.6;
NETWORK
TITLE =Anomalia Asse B Robot Boxing

      U     "M211.4";
      U     "MG";
      UN    DB103.DBX   33.6;
      UN    DB103.DBX   33.7;
      S     DB96.DBX  109.7;
NETWORK
TITLE =Allarme Chiusura Regolazione Pinze Polso

      U     "M216.4";
      U     "MG";
      UN    DB104.DBX   33.6;
      UN    DB104.DBX   33.7;
      S     DB96.DBX  110.0;
NETWORK
TITLE =Tempo di Verifica Allarmi Varie

      U     "EV103";
      UN    "M104.0";
      U     T    122;
      U     "MG";
      U     "M144.6";
      S     DB96.DBX  110.1;
NETWORK
TITLE =Varie Priva di Allarmi

      U(    ;
      U     "EV124";
      UN    "PA";
      O     ;
      U     "EV125";
      UN    "PC";
      O     ;
      U     "EV101";
      UN    "M103.7";
      O     ;
      U     "EV100";
      UN    "RPA";
      O     ;
      U     "EV103";
      UN    "M104.0";
      )     ;
      U     "MG";
      L     S5T#1M;
      SE    T    122;
      NOP   0;
      NOP   0;
      NOP   0;
      NOP   0;
NETWORK
TITLE =Reset Anomalie

      U(    ;
      L     DB96.DBD  106;
      L     L#0;

      ==D   ;
      )     ;
      U(    ;
      L     DB96.DBD  110;
      L     L#0;
      ==D   ;
      )     ;
      U(    ;
      L     DB96.DBW  114;
      L     0;
      ==I   ;
      )     ;
      =     "M144.6";
NETWORK
TITLE =

      U     "PL716";
      O     "M104.5";
      L     S5T#1S;
      SV    "T54";
      U     "T54";
      FP    M    253.0;
      SPBNB M001;
      L     0;
      T     DB96.DBW    0;
      T     DB96.DBW    2;
      T     DB96.DBW    4;
      T     DB96.DBW    6;
      T     DB96.DBW    8;
      T     DB96.DBW   10;
      T     DB96.DBW   12;
      T     DB96.DBW   14;
      T     DB96.DBW   16;
      T     DB96.DBW   18;
      T     DB96.DBW   20;
      T     DB96.DBW   22;
      T     DB96.DBW   24;
      T     DB96.DBW   26;
      T     DB96.DBW   28;
      T     DB96.DBW   30;
      T     DB96.DBW   32;
      T     DB96.DBW   34;
      T     DB96.DBW   36;
      T     DB96.DBW   38;
      T     DB96.DBW   40;
      T     DB96.DBW   42;
      T     DB96.DBW   44;
      T     DB96.DBW   46;
      T     DB96.DBW   48;
      T     DB96.DBW   50;
      T     DB96.DBW   52;
      T     DB96.DBW   54;
      T     DB96.DBW   56;
      T     DB96.DBW   58;
      T     DB96.DBW   60;
      T     DB96.DBW   62;
      T     DB96.DBW   64;
      T     DB96.DBW   66;
      T     DB96.DBW   68;
      T     DB96.DBW   70;
      T     DB96.DBW   72;
      T     DB96.DBW   74;
      T     DB96.DBW   76;
      T     DB96.DBW   78;
      T     DB96.DBW   80;
      T     DB96.DBW   82;
      T     DB96.DBW   84;
      T     DB96.DBW   86;
      T     DB96.DBW   88;
      T     DB96.DBW   90;
      T     DB96.DBW   92;
      T     DB96.DBW   94;
      T     DB96.DBW   96;
      T     DB96.DBW   98;
      T     DB96.DBW  100;
      T     DB96.DBW  102;
      T     DB96.DBW  104;
      T     DB96.DBW  106;
      T     DB96.DBW  108;
      T     DB96.DBW  110;
      T     DB96.DBW  112;
      T     DB96.DBW  114;
      T     DB96.DBW  116;
      T     DB96.DBW  118;
      T     DB96.DBW  120;
      T     DB96.DBW  122;
      T     DB96.DBW  124;
M001: NOP   0;
      L     W#16#0;
      T     DB96.DBW  126;
      T     DB96.DBW  128;
      T     DB96.DBW  130;
      T     DB96.DBW  132;
      T     DB96.DBW  134;
      T     DB96.DBW  136;
      T     DB96.DBW  138;
      T     DB96.DBW  140;
      T     DB96.DBW  142;
      T     DB96.DBW  144;
      T     DB96.DBW  146;
      T     DB96.DBW  148;
      T     DB96.DBW  150;
      T     DB96.DBW  152;
      T     DB96.DBW  154;
      T     DB96.DBW  156;
      T     DB96.DBW  158;
      T     DB96.DBW  160;
      T     DB96.DBW  162;
      T     DB96.DBW  164;
      T     DB96.DBW  166;
      T     DB96.DBW  168;
      T     DB96.DBW  170;
      T     DB96.DBW  172;
      T     DB96.DBW  174;
      T     DB96.DBW  176;
      T     DB96.DBW  178;
      T     DB96.DBW  180;
      T     DB96.DBW  182;
      T     DB96.DBW  184;
      T     DB96.DBW  186;
      T     DB96.DBW  188;
      T     DB96.DBW  190;
      T     DB96.DBW  192;
      T     DB96.DBW  194;
      T     DB96.DBW  196;
      T     DB96.DBW  198;
      T     DB96.DBW  200;
      T     DB96.DBW  206;
      U     "T54";
      SPBNB M002;
      L     W#16#FFFF;
      T     DB96.DBW  126;
      T     DB96.DBW  128;
      T     DB96.DBW  130;
      T     DB96.DBW  132;
      T     DB96.DBW  134;
      T     DB96.DBW  136;
      T     DB96.DBW  138;
      T     DB96.DBW  140;
      T     DB96.DBW  142;
      T     DB96.DBW  144;
      T     DB96.DBW  146;
      T     DB96.DBW  148;
      T     DB96.DBW  150;
      T     DB96.DBW  152;
      T     DB96.DBW  154;
      T     DB96.DBW  156;
      T     DB96.DBW  158;
      T     DB96.DBW  160;
      T     DB96.DBW  162;
      T     DB96.DBW  164;
      T     DB96.DBW  166;
      T     DB96.DBW  168;
      T     DB96.DBW  170;
      T     DB96.DBW  172;
      T     DB96.DBW  174;
      T     DB96.DBW  176;
      T     DB96.DBW  178;
      T     DB96.DBW  180;
      T     DB96.DBW  182;
      T     DB96.DBW  184;
      T     DB96.DBW  186;
      T     DB96.DBW  188;
      T     DB96.DBW  190;
      T     DB96.DBW  192;
      T     DB96.DBW  194;
      T     DB96.DBW  196;
      T     DB96.DBW  198;
      T     DB96.DBW  200;
      T     DB96.DBW  206;
M002: NOP   0;
END_FUNCTION

